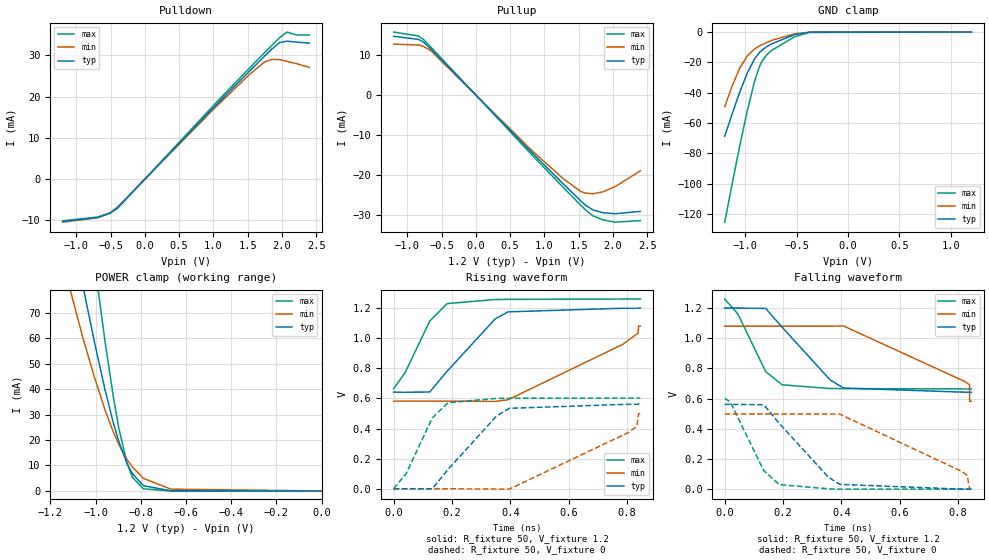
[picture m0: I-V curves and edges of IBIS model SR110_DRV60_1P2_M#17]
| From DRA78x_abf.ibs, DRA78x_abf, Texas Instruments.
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| Model based on original model for DDR_SEIOPB_V
|   Sub model SR110_DRV60_1P2
[model]   SR110_DRV60_1P2_M#17
|[Description]  [1.2V-I/O-X-X]
|   , ,
|[Input Load]
|[Output Drive]
|Voltage   1.2V
|Mode   I/O
Model_type   I/O
Polarity   Non-Inverting
Enable   Active-Low
Vinl =  0.47
Vinh =  0.73
Cref =  15.0000pF
Rref =  100.0000M
Vref =  0V
Vmeas =  0.6
C_comp   2p   2p   2p
[Model Spec]
Vinl   0.47   0.41   0.50
Vinh   0.73   0.67   0.76
[Receiver Thresholds]
Tslew_ac = 5n
Vth = 0.6
Vth_max = 0.63
Vth_min = 0.54
Vinh_ac = 0.22
Vinh_dc = 0.13
Vinl_ac = -0.22
Vinl_dc = -0.13
[Temperature Range]   25   125   -40
[Voltage Range]   1.2   1.08   1.26
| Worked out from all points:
|   slope of the pulldown table from 0 to 0.18 V, typ, clamps not added: 57.2 ohm
|   slope of the pullup table from 0 to 0.18 V, typ, clamps not added: 56.5 ohm
|   GND clamp passes 1 mA (typ) near -0.48 V on its own axis
|   POWER clamp passes 1 mA (typ) near -0.76 V on its own axis
|   rising waveform, R_fixture 50, V_fixture 1.2: 20-80 % time 164ps typ, 322ps min, 88.1ps max; typ from 0.642 V to 1.2 V
|   rising waveform, R_fixture 50, V_fixture 0: 20-80 % time 162ps typ, 307ps min, 87.9ps max; typ from 0 V to 0.562 V
|   falling waveform, R_fixture 50, V_fixture 1.2: 20-80 % time 161ps typ, 295ps min, 88.7ps max; typ from 1.2 V to 0.642 V
|   falling waveform, R_fixture 50, V_fixture 0: 20-80 % time 163ps typ, 312ps min, 89.1ps max; typ from 0.562 V to 0 V
[POWER_clamp]
-1.2V     148.6mA    109.7mA    235.9mA
-1.115V   108mA      79.97mA    170.5mA
-1.055V   80.16mA    59.93mA    125.3mA
-1.006V   59.04mA    45.03mA    90.73mA
-957.6mV  39.59mA    31.69mA    58.49mA
-921.2mV  26.75mA    23.11mA    36.96mA
-897mV    19.41mA    18.26mA    24.7mA
-860.6mV  10.74mA    12.35mA    10.83mA
-836.4mV  6.696mA    9.316mA    5.268mA
-787.9mV  2.052mA    4.939mA    818.3uA
-666.7mV  49.08uA    692.2uA    5.202uA
0V        48.89nA    205.6nA    269.9nA
[Pulldown]
-1.2V     -10.25mA   -10.41mA   -10.07mA
-690.9mV  -9.274mA   -9.358mA   -9.173mA
-509.1mV  -8.227mA   -8.152mA   -8.246mA
-400mV    -6.9mA     -6.78mA    -7.076mA
1.018V    17.59mA    17.2mA     18.12mA
1.527V    26.15mA    25.34mA    26.9mA
1.745V    29.75mA    28.34mA    30.59mA
1.855V    31.52mA    29.01mA    32.41mA
1.964V    33.05mA    28.95mA    34.21mA
2.073V    33.41mA    28.52mA    35.6mA
2.218V    33.15mA    27.94mA    34.88mA
2.4V      32.95mA    27.06mA    34.88mA
[Pullup]
-1.2V     14.78mA    12.82mA    15.83mA
-836.4mV  14mA       12.59mA    14.86mA
-763.6mV  13.3mA     12.22mA    13.97mA
-654.5mV  11.57mA    11.13mA    12.02mA
836.4mV   -14.66mA   -14.11mA   -15.25mA
1.273V    -22.12mA   -20.83mA   -23.01mA
1.527V    -26.37mA   -24.03mA   -27.45mA
1.6V      -27.49mA   -24.48mA   -28.68mA
1.709V    -28.68mA   -24.63mA   -30.17mA
1.855V    -29.39mA   -24.15mA   -31.17mA
2.036V    -29.63mA   -22.8mA    -31.75mA
2.4V      -29.04mA   -18.88mA   -31.34mA
[GND_clamp]
-1.2V     -68.74mA   -49.24mA   -125.5mA
-1.127V   -53.92mA   -35.5mA    -100.1mA
-1.055V   -39.92mA   -23.99mA   -75.5mA
-981.8mV  -27.37mA   -15.83mA   -52.4mA
-909.1mV  -17.63mA   -11.09mA   -32.41mA
-860.6mV  -13.38mA   -9.079mA   -22.59mA
-836.4mV  -11.86mA   -8.241mA   -19.18mA
-787.9mV  -9.515mA   -6.746mA   -14.76mA
-739.4mV  -7.652mA   -5.419mA   -11.95mA
-521.2mV  -1.657mA   -1.168mA   -3.09mA
-375.8mV  -108.2uA   -128.9uA   -198.1uA
1.2V      48.89nA    308.5nA    224.4nA
[Ramp]
dV/dt_f 0.33577288/0.16134658n 0.29997816/0.30428946n 0.35786069/88.819182p
dV/dt_r 0.33946784/0.16323248n 0.30118979/0.3138701n 0.36323897/88.261455p
R_load = 50
[Rising Waveform]
R_fixture = 50
V_fixture = 1.2
V_fixture_min = 1.08
V_fixture_max = 1.26
0s        641.7mV    581.9mV    665mV
39.3ps    641mV      581.9mV    771.3mV
123.8ps   642.6mV    581.8mV    1.114V
183.6ps   781.7mV    581.9mV    1.23V
347.2ps   1.127V     580.4mV    1.257V
391.8ps   1.175V     590.9mV    1.258V
784.8ps   1.199V     958.9mV    1.26V
837.1ps   1.199V     1.033V     1.26V
839.5ps   1.2V       1.08V      1.26V
845.5ps   1.2V       1.08V      1.26V
[Rising Waveform]
R_fixture = 50
V_fixture = 0
V_fixture_min = 0
V_fixture_max = 0
0s        0V         0V         0V
42.9ps    0V         0V         100.9mV
132.3ps   0V         0V         470mV
186.1ps   128.1mV    0V         571.5mV
352.4ps   482.6mV    -2.041mV   600.3mV
396ps     534.2mV    -2.729mV   601mV
804.5ps   561.3mV    373.5mV    602.3mV
833.5ps   561.3mV    415mV      602.3mV
839.3ps   562mV      497.9mV    602.3mV
845.3ps   562mV      497.9mV    602.3mV
[Falling Waveform]
R_fixture = 50
V_fixture = 1.2
V_fixture_min = 1.08
V_fixture_max = 1.26
0s        1.2V       1.08V      1.26V
44.9ps    1.2V       1.08V      1.162V
140.5ps   1.198V     1.08V      778.8mV
197ps     1.073V     1.08V      691.6mV
361.1ps   724.5mV    1.08V      667.1mV
406.8ps   670.4mV    1.082V     666.4mV
822.4ps   642.7mV    713.9mV    664.4mV
839.1ps   642.6mV    692.3mV    664.4mV
839.5ps   641.7mV    581.9mV    664.3mV
845.5ps   641.7mV    581.9mV    664.3mV
[Falling Waveform]
R_fixture = 50
V_fixture = 0
V_fixture_min = 0
V_fixture_max = 0
0s        562mV      497.9mV    601.3mV
18.9ps    562mV      497.9mV    578.9mV
133.8ps   560.1mV    498mV      123.1mV
187.1ps   435.5mV    497.9mV    30.31mV
355.3ps   79.77mV    497.9mV    2.199mV
394ps     31.88mV    497.8mV    0V
813.6ps   0V         116.5mV    0V
831.1ps   0V         91.13mV    0V
839.3ps   0V         0V         0V
845.3ps   0V         0V         0V
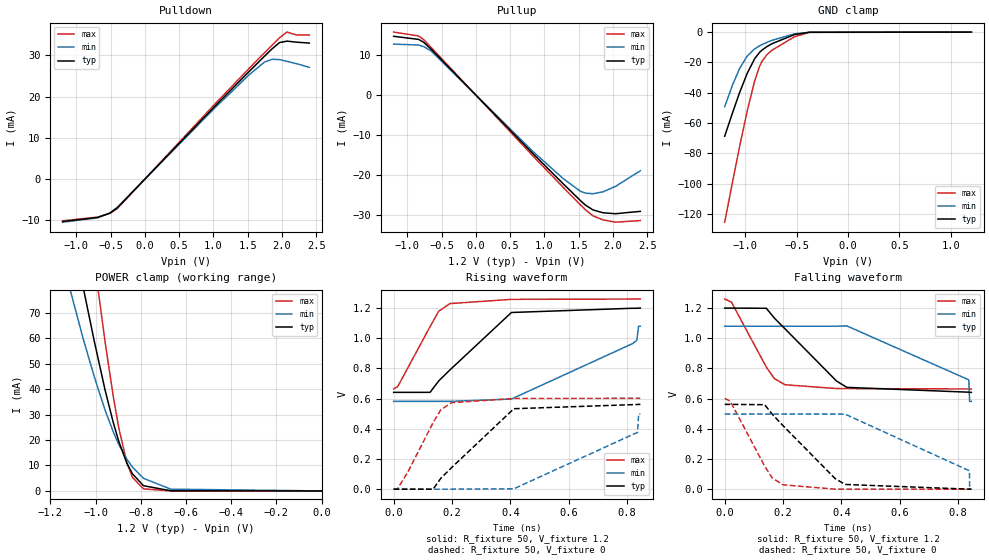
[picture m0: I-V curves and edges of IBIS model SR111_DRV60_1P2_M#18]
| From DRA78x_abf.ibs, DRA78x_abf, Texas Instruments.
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| Model based on original model for DDR_SEIOPB_V
|   Sub model SR111_DRV60_1P2
[model]   SR111_DRV60_1P2_M#18
|[Description]  [1.2V-I/O-X-X]
|   , ,
|[Input Load]
|[Output Drive]
|Voltage   1.2V
|Mode   I/O
Model_type   I/O
Polarity   Non-Inverting
Enable   Active-Low
Vinl =  0.47
Vinh =  0.73
Cref =  15.0000pF
Rref =  100.0000M
Vref =  0V
Vmeas =  0.6
C_comp   2p   2p   2p
[Model Spec]
Vinl   0.47   0.41   0.50
Vinh   0.73   0.67   0.76
[Receiver Thresholds]
Tslew_ac = 5n
Vth = 0.6
Vth_max = 0.63
Vth_min = 0.54
Vinh_ac = 0.22
Vinh_dc = 0.13
Vinl_ac = -0.22
Vinl_dc = -0.13
[Temperature Range]   25   125   -40
[Voltage Range]   1.2   1.08   1.26
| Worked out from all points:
|   slope of the pulldown table from 0 to 0.18 V, typ, clamps not added: 57.2 ohm
|   slope of the pullup table from 0 to 0.18 V, typ, clamps not added: 56.5 ohm
|   GND clamp passes 1 mA (typ) near -0.48 V on its own axis
|   POWER clamp passes 1 mA (typ) near -0.76 V on its own axis
|   rising waveform, R_fixture 50, V_fixture 1.2: 20-80 % time 179ps typ, 347ps min, 95.9ps max; typ from 0.642 V to 1.2 V
|   rising waveform, R_fixture 50, V_fixture 0: 20-80 % time 177ps typ, 316ps min, 95.3ps max; typ from 0 V to 0.562 V
|   falling waveform, R_fixture 50, V_fixture 1.2: 20-80 % time 176ps typ, 286ps min, 96ps max; typ from 1.2 V to 0.642 V
|   falling waveform, R_fixture 50, V_fixture 0: 20-80 % time 178ps typ, 319ps min, 96.7ps max; typ from 0.562 V to 0 V
[POWER_clamp]
-1.2V     148.6mA    109.7mA    235.9mA
-1.115V   108mA      79.97mA    170.5mA
-1.055V   80.16mA    59.93mA    125.3mA
-1.006V   59.04mA    45.03mA    90.73mA
-957.6mV  39.59mA    31.69mA    58.49mA
-921.2mV  26.75mA    23.11mA    36.96mA
-897mV    19.41mA    18.26mA    24.7mA
-860.6mV  10.74mA    12.35mA    10.83mA
-836.4mV  6.696mA    9.316mA    5.268mA
-787.9mV  2.052mA    4.939mA    818.3uA
-666.7mV  49.08uA    692.2uA    5.202uA
0V        48.89nA    205.6nA    269.9nA
[Pulldown]
-1.2V     -10.25mA   -10.41mA   -10.07mA
-690.9mV  -9.274mA   -9.358mA   -9.173mA
-509.1mV  -8.227mA   -8.152mA   -8.246mA
-400mV    -6.9mA     -6.78mA    -7.076mA
1.018V    17.59mA    17.2mA     18.12mA
1.527V    26.15mA    25.34mA    26.9mA
1.745V    29.75mA    28.34mA    30.59mA
1.855V    31.52mA    29.01mA    32.41mA
1.964V    33.05mA    28.95mA    34.21mA
2.073V    33.41mA    28.52mA    35.6mA
2.218V    33.15mA    27.94mA    34.88mA
2.4V      32.95mA    27.06mA    34.88mA
[Pullup]
-1.2V     14.78mA    12.82mA    15.83mA
-836.4mV  14mA       12.59mA    14.86mA
-763.6mV  13.3mA     12.22mA    13.97mA
-654.5mV  11.57mA    11.13mA    12.02mA
836.4mV   -14.66mA   -14.11mA   -15.25mA
1.273V    -22.12mA   -20.83mA   -23.01mA
1.527V    -26.37mA   -24.03mA   -27.45mA
1.6V      -27.49mA   -24.48mA   -28.68mA
1.709V    -28.68mA   -24.63mA   -30.17mA
1.855V    -29.39mA   -24.15mA   -31.17mA
2.036V    -29.63mA   -22.8mA    -31.75mA
2.4V      -29.04mA   -18.88mA   -31.34mA
[GND_clamp]
-1.2V     -68.74mA   -49.24mA   -125.5mA
-1.127V   -53.92mA   -35.5mA    -100.1mA
-1.055V   -39.92mA   -23.99mA   -75.5mA
-981.8mV  -27.37mA   -15.83mA   -52.4mA
-909.1mV  -17.63mA   -11.09mA   -32.41mA
-860.6mV  -13.38mA   -9.079mA   -22.59mA
-836.4mV  -11.86mA   -8.241mA   -19.18mA
-787.9mV  -9.515mA   -6.746mA   -14.76mA
-739.4mV  -7.652mA   -5.419mA   -11.95mA
-521.2mV  -1.657mA   -1.168mA   -3.09mA
-375.8mV  -108.2uA   -128.9uA   -198.1uA
1.2V      48.89nA    308.5nA    224.4nA
[Ramp]
dV/dt_f 0.33583007/0.1769161n 0.29997968/0.32924919n 0.35787335/96.135356p
dV/dt_r 0.33951667/0.17854918n  0.3012481/0.33926419n 0.36316246/95.688566p
R_load = 50
[Rising Waveform]
R_fixture = 50
V_fixture = 1.2
V_fixture_min = 1.08
V_fixture_max = 1.26
0s        641.7mV    581.9mV    664.5mV
14.1ps    641.6mV    581.9mV    680.4mV
124.7ps   641.7mV    581.9mV    1.077V
154.4ps   717.3mV    581.8mV    1.179V
192.8ps   790.1mV    581.9mV    1.23V
403.6ps   1.171V     597.3mV    1.258V
818.3ps   1.199V     964.4mV    1.26V
833.3ps   1.199V     985.9mV    1.26V
839.3ps   1.2V       1.08V      1.26V
845.3ps   1.2V       1.08V      1.26V
[Rising Waveform]
R_fixture = 50
V_fixture = 0
V_fixture_min = 0
V_fixture_max = 0
0s        0V         0V         0V
12.5ps    0V         0V         0V
48.1ps    0V         0V         111.8mV
135.3ps   0V         0V         441.3mV
161.4ps   71.81mV    0V         525.4mV
198.1ps   142.1mV    0V         573.1mV
411.9ps   533.2mV    2.656mV    601.1mV
835.9ps   561.3mV    376.8mV    602.3mV
839.5ps   562mV      497.9mV    602.3mV
845.5ps   562mV      497.9mV    602.3mV
[Falling Waveform]
R_fixture = 50
V_fixture = 1.2
V_fixture_min = 1.08
V_fixture_max = 1.26
0s        1.2V       1.08V      1.26V
23ps      1.2V       1.08V      1.24V
142.7ps   1.199V     1.08V      808.8mV
170.1ps   1.134V     1.08V      733.2mV
206.6ps   1.063V     1.08V      692.2mV
383.3ps   716.6mV    1.08V      666.9mV
418.6ps   674.7mV    1.082V     666.3mV
836.6ps   642.7mV    724.4mV    664.4mV
839.3ps   641.7mV    581.9mV    664.3mV
845.3ps   641.7mV    581.9mV    664.3mV
[Falling Waveform]
R_fixture = 50
V_fixture = 0
V_fixture_min = 0
V_fixture_max = 0
0s        562mV      497.9mV    601.7mV
18.7ps    562mV      497.9mV    583.7mV
136.9ps   559.8mV    498mV      153.2mV
163ps     496.6mV    498mV      74.11mV
199.9ps   420.7mV    497.9mV    28.81mV
378.6ps   70.06mV    498mV      0V
413ps     31.18mV    496.7mV    0V
838.8ps   0V         121.7mV    0V
839.5ps   0V         0V         0V
845.5ps   0V         0V         0V
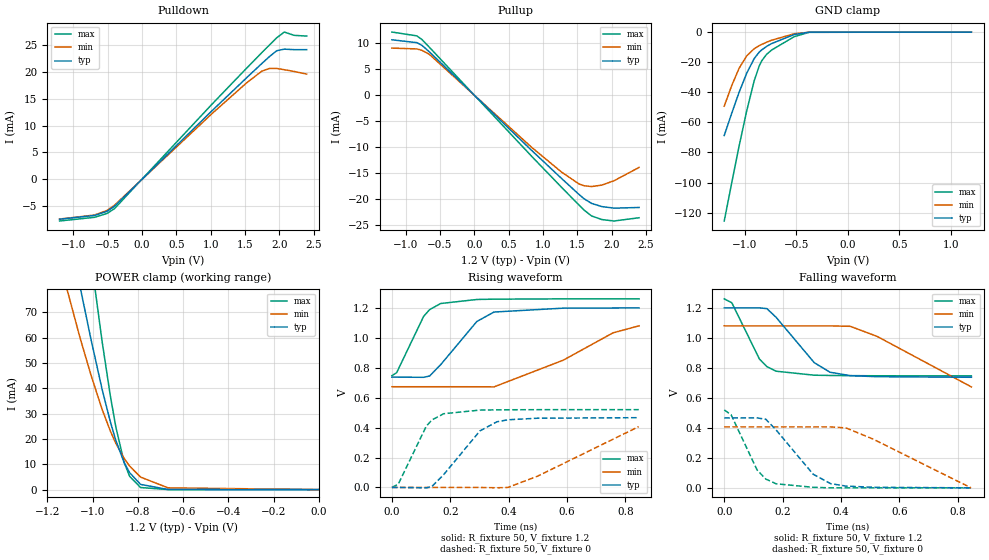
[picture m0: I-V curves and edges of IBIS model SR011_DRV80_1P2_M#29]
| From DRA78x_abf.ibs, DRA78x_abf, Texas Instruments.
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| Model based on original model for DDR_SEIOPB_V
|   Sub model SR011_DRV80_1P2
[model]   SR011_DRV80_1P2_M#29
|[Description]  [1.2V-I/O-X-X]
|   , ,
|[Input Load]
|[Output Drive]
|Voltage   1.2V
|Mode   I/O
Model_type   I/O
Polarity   Non-Inverting
Enable   Active-Low
Vinl =  0.47
Vinh =  0.73
Cref =  15.0000pF
Rref =  100.0000M
Vref =  0V
Vmeas =  0.6
C_comp   2p   2p   2p
[Model Spec]
Vinl   0.47   0.41   0.50
Vinh   0.73   0.67   0.76
[Receiver Thresholds]
Tslew_ac = 5n
Vth = 0.6
Vth_max = 0.63
Vth_min = 0.54
Vinh_ac = 0.22
Vinh_dc = 0.13
Vinl_ac = -0.22
Vinl_dc = -0.13
[Temperature Range]   25   125   -40
[Voltage Range]   1.2   1.08   1.26
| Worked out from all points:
|   slope of the pulldown table from 0 to 0.18 V, typ, clamps not added: 79.2 ohm
|   slope of the pullup table from 0 to 0.18 V, typ, clamps not added: 78.2 ohm
|   GND clamp passes 1 mA (typ) near -0.48 V on its own axis
|   POWER clamp passes 1 mA (typ) near -0.76 V on its own axis
|   rising waveform, R_fixture 50, V_fixture 1.2: 20-80 % time 119ps typ, 250ps min, 78ps max; typ from 0.737 V to 1.2 V
|   rising waveform, R_fixture 50, V_fixture 0: 20-80 % time 119ps typ, 247ps min, 78.2ps max; typ from 0 V to 0.466 V
|   falling waveform, R_fixture 50, V_fixture 1.2: 20-80 % time 120ps typ, 240ps min, 79.1ps max; typ from 1.2 V to 0.737 V
|   falling waveform, R_fixture 50, V_fixture 0: 20-80 % time 120ps typ, 242ps min, 78ps max; typ from 0.466 V to 0 V
[POWER_clamp]
-1.2V     148.6mA    109.7mA    235.9mA
-1.115V   108mA      79.97mA    170.5mA
-1.055V   80.16mA    59.93mA    125.3mA
-1.006V   59.04mA    45.03mA    90.73mA
-957.6mV  39.59mA    31.69mA    58.49mA
-921.2mV  26.75mA    23.11mA    36.96mA
-897mV    19.41mA    18.26mA    24.7mA
-860.6mV  10.74mA    12.35mA    10.83mA
-836.4mV  6.696mA    9.316mA    5.268mA
-787.9mV  2.052mA    4.939mA    818.3uA
-666.7mV  49.08uA    692.2uA    5.202uA
0V        48.89nA    205.6nA    269.9nA
[Pulldown]
-1.2V     -7.405mA   -7.369mA   -7.736mA
-690.9mV  -6.7mA     -6.627mA   -7.049mA
-509.1mV  -5.944mA   -5.774mA   -6.338mA
-400mV    -4.987mA   -4.803mA   -5.44mA
1.018V    12.71mA    12.18mA    13.93mA
1.527V    18.9mA     17.95mA    20.68mA
1.745V    21.5mA     20.08mA    23.52mA
1.855V    22.78mA    20.59mA    24.92mA
1.964V    23.89mA    20.6mA     26.3mA
2.073V    24.18mA    20.36mA    27.36mA
2.218V    24.09mA    20.04mA    26.74mA
2.4V      24.09mA    19.54mA    26.61mA
[Pullup]
-1.2V     10.67mA    9.076mA    12.16mA
-836.4mV  10.12mA    8.913mA    11.42mA
-763.6mV  9.612mA    8.654mA    10.74mA
-654.5mV  8.359mA    7.881mA    9.24mA
836.4mV   -10.59mA   -9.996mA   -11.72mA
1.273V    -15.99mA   -14.76mA   -17.69mA
1.527V    -19.06mA   -17.03mA   -21.1mA
1.6V      -19.87mA   -17.37mA   -22.05mA
1.709V    -20.76mA   -17.52mA   -23.17mA
1.855V    -21.36mA   -17.25mA   -23.85mA
2.036V    -21.67mA   -16.4mA    -24.14mA
2.4V      -21.54mA   -13.85mA   -23.51mA
[GND_clamp]
-1.2V     -68.74mA   -49.24mA   -125.5mA
-1.127V   -53.92mA   -35.5mA    -100.1mA
-1.055V   -39.92mA   -23.99mA   -75.5mA
-981.8mV  -27.37mA   -15.83mA   -52.4mA
-909.1mV  -17.63mA   -11.09mA   -32.41mA
-860.6mV  -13.38mA   -9.079mA   -22.59mA
-836.4mV  -11.86mA   -8.241mA   -19.18mA
-787.9mV  -9.515mA   -6.746mA   -14.76mA
-739.4mV  -7.652mA   -5.419mA   -11.95mA
-521.2mV  -1.657mA   -1.168mA   -3.09mA
-375.8mV  -108.2uA   -128.9uA   -198.1uA
1.2V      48.89nA    308.5nA    224.4nA
[Ramp]
dV/dt_f 0.27812768/0.11982563n 0.24490387/0.24113691n 0.30863571/79.209756p
dV/dt_r 0.28141067/0.11932311n 0.24546317/0.24930007n 0.31390913/78.491417p
R_load = 50
[Rising Waveform]
R_fixture = 50
V_fixture = 1.2
V_fixture_min = 1.08
V_fixture_max = 1.26
0s        737.2mV    673mV      746.6mV
16.3ps    737mV      672.9mV    766.8mV
108.7ps   735.9mV    672.9mV    1.143V
129.1ps   744.6mV    672.9mV    1.188V
167.1ps   820.4mV    672.9mV    1.229V
291ps     1.109V     672.8mV    1.256V
349.6ps   1.172V     671.9mV    1.258V
587.3ps   1.198V     850.6mV    1.26V
757.2ps   1.199V     1.033V     1.26V
846.5ps   1.2V       1.08V      1.26V
[Rising Waveform]
R_fixture = 50
V_fixture = 0
V_fixture_min = 0
V_fixture_max = 0
0s        0V         0V         0V
21.9ps    0V         0V         22.34mV
117.9ps   -2.635mV   0V         409.9mV
137.4ps   7.166mV    0V         451.1mV
177.3ps   85.48mV    0V         492.6mV
301.6ps   378mV      0V         516.9mV
359.6ps   438.7mV    -2.185mV   518.5mV
397ps     452.2mV    0V         519.1mV
498.9ps   462.6mV    75.31mV    519.6mV
845.3ps   466.2mV    406.3mV    520mV
[Falling Waveform]
R_fixture = 50
V_fixture = 1.2
V_fixture_min = 1.08
V_fixture_max = 1.26
0s        1.2V       1.08V      1.26V
26ps      1.2V       1.08V      1.234V
120.4ps   1.2V       1.08V      859.3mV
146.1ps   1.195V     1.08V      808.4mV
177.7ps   1.137V     1.08V      777.7mV
308.4ps   834.4mV    1.08V      751mV
362.3ps   770.9mV    1.08V      749.3mV
431.4ps   748mV      1.077V     748.1mV
523.4ps   741.1mV    1.01V      747.2mV
846.5ps   737.2mV    673mV      746.4mV
[Falling Waveform]
R_fixture = 50
V_fixture = 0
V_fixture_min = 0
V_fixture_max = 0
0s        466.2mV    406.3mV    519.6mV
23.5ps    466.4mV    406.4mV    487.1mV
112.8ps   466.2mV    406.4mV    118.1mV
142.5ps   457.1mV    406.4mV    58.56mV
177.7ps   385.8mV    406.4mV    27.03mV
304.6ps   90.89mV    406.4mV    3.513mV
364.2ps   28.09mV    406.5mV    0V
416.7ps   11.74mV    399.8mV    0V
510.5ps   3.634mV    324.5mV    0V
845.3ps   0V         0V         0V
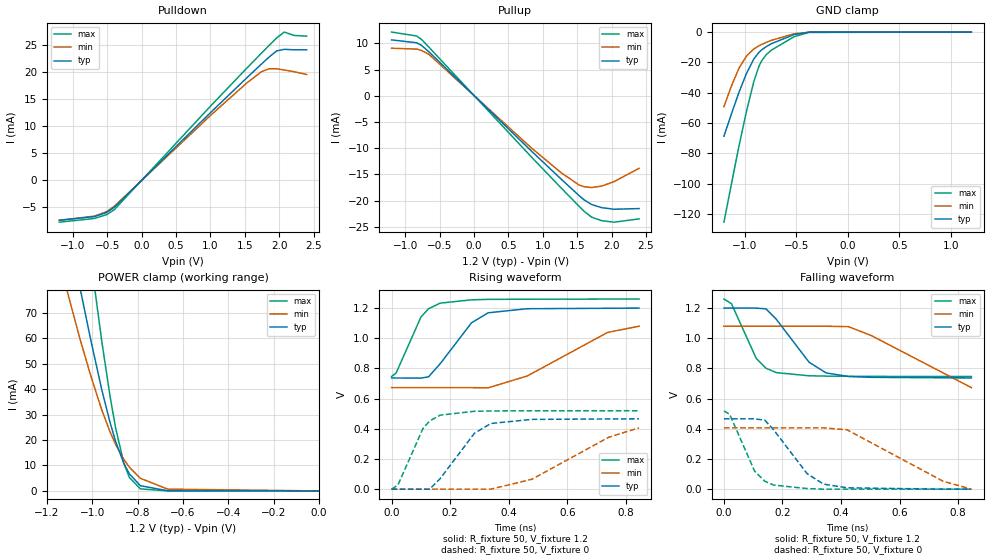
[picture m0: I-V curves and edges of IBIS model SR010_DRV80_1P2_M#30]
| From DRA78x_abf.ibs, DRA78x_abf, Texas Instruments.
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| Model based on original model for DDR_SEIOPB_V
|   Sub model SR010_DRV80_1P2
[model]   SR010_DRV80_1P2_M#30
|[Description]  [1.2V-I/O-X-X]
|   , ,
|[Input Load]
|[Output Drive]
|Voltage   1.2V
|Mode   I/O
Model_type   I/O
Polarity   Non-Inverting
Enable   Active-Low
Vinl =  0.47
Vinh =  0.73
Cref =  15.0000pF
Rref =  100.0000M
Vref =  0V
Vmeas =  0.6
C_comp   2p   2p   2p
[Model Spec]
Vinl   0.47   0.41   0.50
Vinh   0.73   0.67   0.76
[Receiver Thresholds]
Tslew_ac = 5n
Vth = 0.6
Vth_max = 0.63
Vth_min = 0.54
Vinh_ac = 0.22
Vinh_dc = 0.13
Vinl_ac = -0.22
Vinl_dc = -0.13
[Temperature Range]   25   125   -40
[Voltage Range]   1.2   1.08   1.26
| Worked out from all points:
|   slope of the pulldown table from 0 to 0.18 V, typ, clamps not added: 79.2 ohm
|   slope of the pullup table from 0 to 0.18 V, typ, clamps not added: 78.2 ohm
|   GND clamp passes 1 mA (typ) near -0.48 V on its own axis
|   POWER clamp passes 1 mA (typ) near -0.76 V on its own axis
|   rising waveform, R_fixture 50, V_fixture 1.2: 20-80 % time 110ps typ, 232ps min, 72.8ps max; typ from 0.737 V to 1.2 V
|   rising waveform, R_fixture 50, V_fixture 0: 20-80 % time 110ps typ, 230ps min, 72.9ps max; typ from 0 V to 0.466 V
|   falling waveform, R_fixture 50, V_fixture 1.2: 20-80 % time 111ps typ, 223ps min, 74.2ps max; typ from 1.2 V to 0.737 V
|   falling waveform, R_fixture 50, V_fixture 0: 20-80 % time 111ps typ, 224ps min, 73.1ps max; typ from 0.466 V to 0 V
[POWER_clamp]
-1.2V     148.6mA    109.7mA    235.9mA
-1.115V   108mA      79.97mA    170.5mA
-1.055V   80.16mA    59.93mA    125.3mA
-1.006V   59.04mA    45.03mA    90.73mA
-957.6mV  39.59mA    31.69mA    58.49mA
-921.2mV  26.75mA    23.11mA    36.96mA
-897mV    19.41mA    18.26mA    24.7mA
-860.6mV  10.74mA    12.35mA    10.83mA
-836.4mV  6.696mA    9.316mA    5.268mA
-787.9mV  2.052mA    4.939mA    818.3uA
-666.7mV  49.08uA    692.2uA    5.202uA
0V        48.89nA    205.6nA    269.9nA
[Pulldown]
-1.2V     -7.405mA   -7.369mA   -7.736mA
-690.9mV  -6.7mA     -6.627mA   -7.049mA
-509.1mV  -5.944mA   -5.774mA   -6.338mA
-400mV    -4.987mA   -4.803mA   -5.44mA
1.018V    12.71mA    12.18mA    13.93mA
1.527V    18.9mA     17.95mA    20.68mA
1.745V    21.5mA     20.08mA    23.52mA
1.855V    22.78mA    20.59mA    24.92mA
1.964V    23.89mA    20.6mA     26.3mA
2.073V    24.18mA    20.36mA    27.36mA
2.218V    24.09mA    20.04mA    26.74mA
2.4V      24.09mA    19.54mA    26.61mA
[Pullup]
-1.2V     10.67mA    9.076mA    12.16mA
-836.4mV  10.12mA    8.913mA    11.42mA
-763.6mV  9.612mA    8.654mA    10.74mA
-654.5mV  8.359mA    7.881mA    9.24mA
836.4mV   -10.59mA   -9.996mA   -11.72mA
1.273V    -15.99mA   -14.76mA   -17.69mA
1.527V    -19.06mA   -17.03mA   -21.1mA
1.6V      -19.87mA   -17.37mA   -22.05mA
1.709V    -20.76mA   -17.52mA   -23.17mA
1.855V    -21.36mA   -17.25mA   -23.85mA
2.036V    -21.67mA   -16.4mA    -24.14mA
2.4V      -21.54mA   -13.85mA   -23.51mA
[GND_clamp]
-1.2V     -68.74mA   -49.24mA   -125.5mA
-1.127V   -53.92mA   -35.5mA    -100.1mA
-1.055V   -39.92mA   -23.99mA   -75.5mA
-981.8mV  -27.37mA   -15.83mA   -52.4mA
-909.1mV  -17.63mA   -11.09mA   -32.41mA
-860.6mV  -13.38mA   -9.079mA   -22.59mA
-836.4mV  -11.86mA   -8.241mA   -19.18mA
-787.9mV  -9.515mA   -6.746mA   -14.76mA
-739.4mV  -7.652mA   -5.419mA   -11.95mA
-521.2mV  -1.657mA   -1.168mA   -3.09mA
-375.8mV  -108.2uA   -128.9uA   -198.1uA
1.2V      48.89nA    308.5nA    224.4nA
[Ramp]
dV/dt_f 0.27808599/0.11117335n 0.24487076/0.22409488n 0.30862439/74.272178p
dV/dt_r 0.28139213/0.11029676n 0.24544543/0.23162482n 0.31405468/73.198538p
R_load = 50
[Rising Waveform]
R_fixture = 50
V_fixture = 1.2
V_fixture_min = 1.08
V_fixture_max = 1.26
0s        737.2mV    673mV      747.1mV
15.4ps    736.9mV    672.9mV    770mV
100.5ps   736mV      672.9mV    1.142V
126.3ps   744.8mV    672.9mV    1.196V
166ps     831.5mV    672.9mV    1.233V
273.2ps   1.103V     672.8mV    1.255V
330ps     1.169V     671.9mV    1.258V
463.2ps   1.196V     749.9mV    1.259V
738.1ps   1.199V     1.039V     1.26V
845.5ps   1.2V       1.08V      1.26V
[Rising Waveform]
R_fixture = 50
V_fixture = 0
V_fixture_min = 0
V_fixture_max = 0
0s        0V         0V         0V
21.7ps    0V         0V         27.79mV
107.3ps   0V         0V         402.7mV
130ps     0V         0V         452.2mV
165.9ps   69.85mV    0V         490.5mV
282.9ps   370.2mV    0V         516.4mV
339.2ps   435.4mV    0V         518.3mV
479.1ps   462.4mV    65.49mV    519.5mV
742.6ps   465.5mV    344.8mV    520mV
845.3ps   466.2mV    406.3mV    520mV
[Falling Waveform]
R_fixture = 50
V_fixture = 1.2
V_fixture_min = 1.08
V_fixture_max = 1.26
0s        1.2V       1.08V      1.26V
25.5ps    1.2V       1.08V      1.23V
110.5ps   1.2V       1.08V      866.2mV
143.4ps   1.195V     1.08V      802mV
178.5ps   1.127V     1.08V      772.6mV
290.6ps   841.9mV    1.08V      751.5mV
349ps     770.4mV    1.08V      749.4mV
425.8ps   746.8mV    1.077V     748.1mV
504.7ps   741.2mV    1.017V     747.3mV
845.5ps   737.2mV    673mV      746.4mV
[Falling Waveform]
R_fixture = 50
V_fixture = 0
V_fixture_min = 0
V_fixture_max = 0
0s        466.2mV    406.3mV    519.2mV
19.5ps    466.4mV    406.4mV    496.3mV
104.8ps   466.1mV    406.4mV    119.5mV
139.8ps   457.1mV    406.4mV    52.34mV
169.9ps   393.3mV    406.4mV    27.06mV
284.2ps   102.8mV    406.4mV    4.039mV
340.2ps   33.58mV    406.4mV    0V
420.6ps   8.983mV    393.5mV    0V
748.2ps   0V         53.19mV    0V
845.3ps   0V         0V         0V
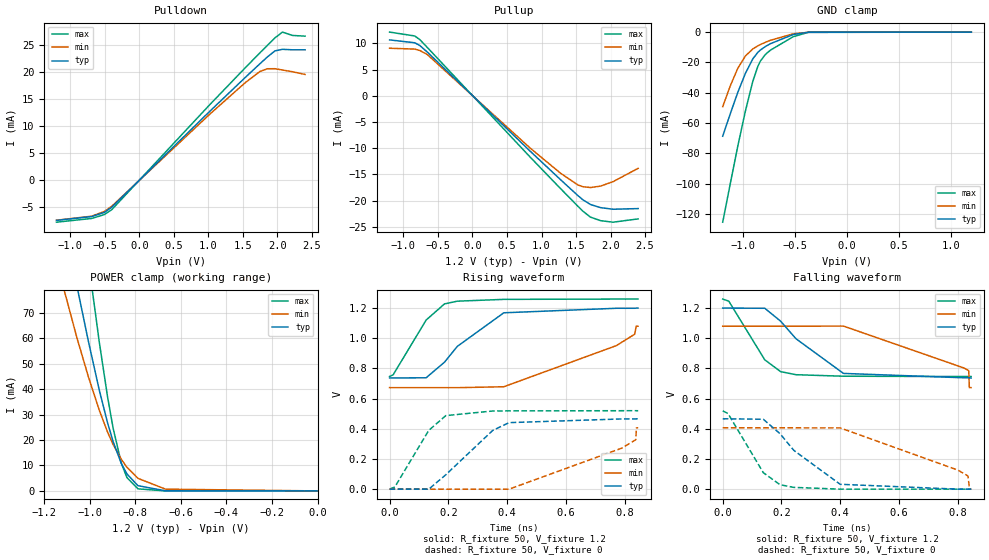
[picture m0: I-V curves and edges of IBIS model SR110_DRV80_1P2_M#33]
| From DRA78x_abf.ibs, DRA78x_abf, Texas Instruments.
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| Model based on original model for DDR_SEIOPB_V
|   Sub model SR110_DRV80_1P2
[model]   SR110_DRV80_1P2_M#33
|[Description]  [1.2V-I/O-X-X]
|   , ,
|[Input Load]
|[Output Drive]
|Voltage   1.2V
|Mode   I/O
Model_type   I/O
Polarity   Non-Inverting
Enable   Active-Low
Vinl =  0.47
Vinh =  0.73
Cref =  15.0000pF
Rref =  100.0000M
Vref =  0V
Vmeas =  0.6
C_comp   2p   2p   2p
[Model Spec]
Vinl   0.47   0.41   0.50
Vinh   0.73   0.67   0.76
[Receiver Thresholds]
Tslew_ac = 5n
Vth = 0.6
Vth_max = 0.63
Vth_min = 0.54
Vinh_ac = 0.22
Vinh_dc = 0.13
Vinl_ac = -0.22
Vinl_dc = -0.13
[Temperature Range]   25   125   -40
[Voltage Range]   1.2   1.08   1.26
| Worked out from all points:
|   slope of the pulldown table from 0 to 0.18 V, typ, clamps not added: 79.2 ohm
|   slope of the pullup table from 0 to 0.18 V, typ, clamps not added: 78.2 ohm
|   GND clamp passes 1 mA (typ) near -0.48 V on its own axis
|   POWER clamp passes 1 mA (typ) near -0.76 V on its own axis
|   rising waveform, R_fixture 50, V_fixture 1.2: 20-80 % time 155ps typ, 308ps min, 99ps max; typ from 0.737 V to 1.2 V
|   rising waveform, R_fixture 50, V_fixture 0: 20-80 % time 152ps typ, 303ps min, 98.6ps max; typ from 0 V to 0.466 V
|   falling waveform, R_fixture 50, V_fixture 1.2: 20-80 % time 152ps typ, 272ps min, 99ps max; typ from 1.2 V to 0.737 V
|   falling waveform, R_fixture 50, V_fixture 0: 20-80 % time 155ps typ, 299ps min, 98.6ps max; typ from 0.466 V to 0 V
[POWER_clamp]
-1.2V     148.6mA    109.7mA    235.9mA
-1.115V   108mA      79.97mA    170.5mA
-1.055V   80.16mA    59.93mA    125.3mA
-1.006V   59.04mA    45.03mA    90.73mA
-957.6mV  39.59mA    31.69mA    58.49mA
-921.2mV  26.75mA    23.11mA    36.96mA
-897mV    19.41mA    18.26mA    24.7mA
-860.6mV  10.74mA    12.35mA    10.83mA
-836.4mV  6.696mA    9.316mA    5.268mA
-787.9mV  2.052mA    4.939mA    818.3uA
-666.7mV  49.08uA    692.2uA    5.202uA
0V        48.89nA    205.6nA    269.9nA
[Pulldown]
-1.2V     -7.405mA   -7.369mA   -7.736mA
-690.9mV  -6.7mA     -6.627mA   -7.049mA
-509.1mV  -5.944mA   -5.774mA   -6.338mA
-400mV    -4.987mA   -4.803mA   -5.44mA
1.018V    12.71mA    12.18mA    13.93mA
1.527V    18.9mA     17.95mA    20.68mA
1.745V    21.5mA     20.08mA    23.52mA
1.855V    22.78mA    20.59mA    24.92mA
1.964V    23.89mA    20.6mA     26.3mA
2.073V    24.18mA    20.36mA    27.36mA
2.218V    24.09mA    20.04mA    26.74mA
2.4V      24.09mA    19.54mA    26.61mA
[Pullup]
-1.2V     10.67mA    9.076mA    12.16mA
-836.4mV  10.12mA    8.913mA    11.42mA
-763.6mV  9.612mA    8.654mA    10.74mA
-654.5mV  8.359mA    7.881mA    9.24mA
836.4mV   -10.59mA   -9.996mA   -11.72mA
1.273V    -15.99mA   -14.76mA   -17.69mA
1.527V    -19.06mA   -17.03mA   -21.1mA
1.6V      -19.87mA   -17.37mA   -22.05mA
1.709V    -20.76mA   -17.52mA   -23.17mA
1.855V    -21.36mA   -17.25mA   -23.85mA
2.036V    -21.67mA   -16.4mA    -24.14mA
2.4V      -21.54mA   -13.85mA   -23.51mA
[GND_clamp]
-1.2V     -68.74mA   -49.24mA   -125.5mA
-1.127V   -53.92mA   -35.5mA    -100.1mA
-1.055V   -39.92mA   -23.99mA   -75.5mA
-981.8mV  -27.37mA   -15.83mA   -52.4mA
-909.1mV  -17.63mA   -11.09mA   -32.41mA
-860.6mV  -13.38mA   -9.079mA   -22.59mA
-836.4mV  -11.86mA   -8.241mA   -19.18mA
-787.9mV  -9.515mA   -6.746mA   -14.76mA
-739.4mV  -7.652mA   -5.419mA   -11.95mA
-521.2mV  -1.657mA   -1.168mA   -3.09mA
-375.8mV  -108.2uA   -128.9uA   -198.1uA
1.2V      48.89nA    308.5nA    224.4nA
[Ramp]
dV/dt_f 0.27821403/0.15270574n 0.24499218/0.2978185n 0.30873683/99.20106p
dV/dt_r 0.28134874/0.15322759n 0.24553615/0.30567669n 0.31391762/99.122188p
R_load = 50
[Rising Waveform]
R_fixture = 50
V_fixture = 1.2
V_fixture_min = 1.08
V_fixture_max = 1.26
0s        737.2mV    673mV      746.8mV
12.4ps    737.1mV    672.9mV    758.7mV
124.4ps   738.3mV    672.9mV    1.121V
186.9ps   841.7mV    673mV      1.228V
230.6ps   946.5mV    672.7mV    1.246V
388.7ps   1.169V     678.8mV    1.258V
771.9ps   1.199V     951.5mV    1.26V
834.1ps   1.199V     1.027V     1.26V
839.3ps   1.2V       1.08V      1.26V
845.3ps   1.2V       1.08V      1.26V
[Rising Waveform]
R_fixture = 50
V_fixture = 0
V_fixture_min = 0
V_fixture_max = 0
0s        0V         0V         0V
17.9ps    0V         0V         14.6mV
133.3ps   0V         0V         389.6mV
191.5ps   95.85mV    0V         487.6mV
350.8ps   389mV      0V         518.1mV
406.6ps   441mV      0V         518.9mV
790.8ps   465.5mV    272.3mV    520mV
837.9ps   465.7mV    327.9mV    520.1mV
840.1ps   466.2mV    406.3mV    520mV
846.1ps   466.2mV    406.3mV    520mV
[Falling Waveform]
R_fixture = 50
V_fixture = 1.2
V_fixture_min = 1.08
V_fixture_max = 1.26
0s        1.2V       1.08V      1.26V
20.7ps    1.2V       1.08V      1.246V
143.1ps   1.199V     1.08V      857.4mV
197.4ps   1.113V     1.08V      778.8mV
249.6ps   996.6mV    1.08V      758.6mV
411ps     767.2mV    1.081V     748.6mV
821ps     738.2mV    803.2mV    746.4mV
837.3ps   738.2mV    785.8mV    746.4mV
839.3ps   737.2mV    673mV      746.4mV
845.3ps   737.2mV    673mV      746.4mV
[Falling Waveform]
R_fixture = 50
V_fixture = 0
V_fixture_min = 0
V_fixture_max = 0
0s        466.2mV    406.3mV    519.1mV
17.9ps    466.3mV    406.4mV    501.7mV
138.2ps   463.3mV    406.4mV    109.3mV
194.9ps   368mV      406.4mV    29.61mV
242.2ps   256.8mV    406.4mV    11.79mV
399.8ps   32.28mV    406mV      0V
800.8ps   0V         126mV      0V
834.8ps   0V         87.1mV     0V
840.1ps   0V         0V         0V
846.1ps   0V         0V         0V
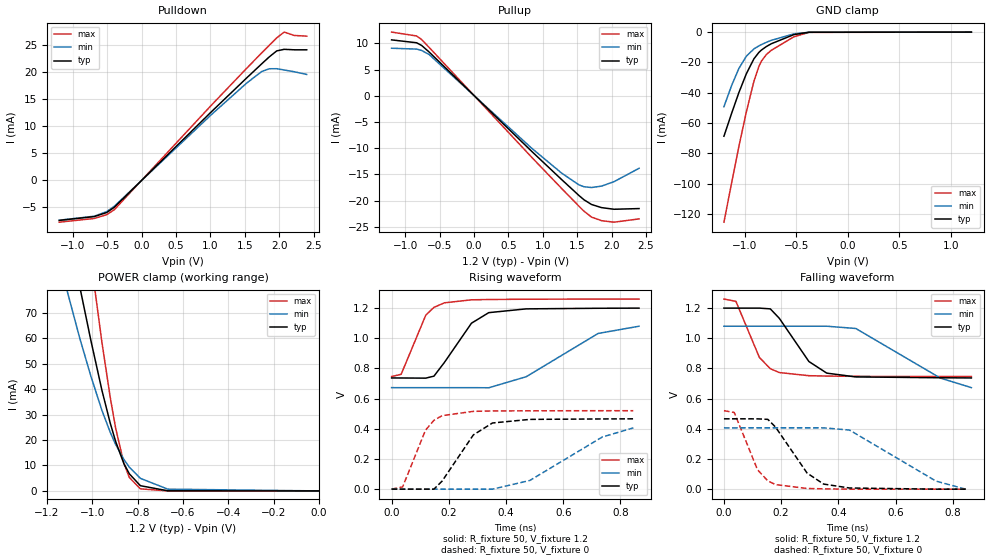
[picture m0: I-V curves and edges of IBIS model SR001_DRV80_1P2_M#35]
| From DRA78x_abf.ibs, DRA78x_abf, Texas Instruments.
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| Model based on original model for DDR_SEIOPB_V
|   Sub model SR001_DRV80_1P2
[model]   SR001_DRV80_1P2_M#35
|[Description]  [1.2V-I/O-X-X]
|   , ,
|[Input Load]
|[Output Drive]
|Voltage   1.2V
|Mode   I/O
Model_type   I/O
Polarity   Non-Inverting
Enable   Active-Low
Vinl =  0.47
Vinh =  0.73
Cref =  15.0000pF
Rref =  100.0000M
Vref =  0V
Vmeas =  0.6
C_comp   2p   2p   2p
[Model Spec]
Vinl   0.47   0.41   0.50
Vinh   0.73   0.67   0.76
[Receiver Thresholds]
Tslew_ac = 5n
Vth = 0.6
Vth_max = 0.63
Vth_min = 0.54
Vinh_ac = 0.22
Vinh_dc = 0.13
Vinl_ac = -0.22
Vinl_dc = -0.13
[Temperature Range]   25   125   -40
[Voltage Range]   1.2   1.08   1.26
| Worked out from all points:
|   slope of the pulldown table from 0 to 0.18 V, typ, clamps not added: 79.2 ohm
|   slope of the pullup table from 0 to 0.18 V, typ, clamps not added: 78.2 ohm
|   GND clamp passes 1 mA (typ) near -0.48 V on its own axis
|   POWER clamp passes 1 mA (typ) near -0.76 V on its own axis
|   rising waveform, R_fixture 50, V_fixture 1.2: 20-80 % time 102ps typ, 213ps min, 68.5ps max; typ from 0.737 V to 1.2 V
|   rising waveform, R_fixture 50, V_fixture 0: 20-80 % time 102ps typ, 212ps min, 68.6ps max; typ from 0 V to 0.466 V
|   falling waveform, R_fixture 50, V_fixture 1.2: 20-80 % time 103ps typ, 207ps min, 70.4ps max; typ from 1.2 V to 0.737 V
|   falling waveform, R_fixture 50, V_fixture 0: 20-80 % time 103ps typ, 207ps min, 69.2ps max; typ from 0.466 V to 0 V
[POWER_clamp]
-1.2V     148.6mA    109.7mA    235.9mA
-1.115V   108mA      79.97mA    170.5mA
-1.055V   80.16mA    59.93mA    125.3mA
-1.006V   59.04mA    45.03mA    90.73mA
-957.6mV  39.59mA    31.69mA    58.49mA
-921.2mV  26.75mA    23.11mA    36.96mA
-897mV    19.41mA    18.26mA    24.7mA
-860.6mV  10.74mA    12.35mA    10.83mA
-836.4mV  6.696mA    9.316mA    5.268mA
-787.9mV  2.052mA    4.939mA    818.3uA
-666.7mV  49.08uA    692.2uA    5.202uA
0V        48.89nA    205.6nA    269.9nA
[Pulldown]
-1.2V     -7.405mA   -7.369mA   -7.736mA
-690.9mV  -6.7mA     -6.627mA   -7.049mA
-509.1mV  -5.944mA   -5.774mA   -6.338mA
-400mV    -4.987mA   -4.803mA   -5.44mA
1.018V    12.71mA    12.18mA    13.93mA
1.527V    18.9mA     17.95mA    20.68mA
1.745V    21.5mA     20.08mA    23.52mA
1.855V    22.78mA    20.59mA    24.92mA
1.964V    23.89mA    20.6mA     26.3mA
2.073V    24.18mA    20.36mA    27.36mA
2.218V    24.09mA    20.04mA    26.74mA
2.4V      24.09mA    19.54mA    26.61mA
[Pullup]
-1.2V     10.67mA    9.076mA    12.16mA
-836.4mV  10.12mA    8.913mA    11.42mA
-763.6mV  9.612mA    8.654mA    10.74mA
-654.5mV  8.359mA    7.881mA    9.24mA
836.4mV   -10.59mA   -9.996mA   -11.72mA
1.273V    -15.99mA   -14.76mA   -17.69mA
1.527V    -19.06mA   -17.03mA   -21.1mA
1.6V      -19.87mA   -17.37mA   -22.05mA
1.709V    -20.76mA   -17.52mA   -23.17mA
1.855V    -21.36mA   -17.25mA   -23.85mA
2.036V    -21.67mA   -16.4mA    -24.14mA
2.4V      -21.54mA   -13.85mA   -23.51mA
[GND_clamp]
-1.2V     -68.74mA   -49.24mA   -125.5mA
-1.127V   -53.92mA   -35.5mA    -100.1mA
-1.055V   -39.92mA   -23.99mA   -75.5mA
-981.8mV  -27.37mA   -15.83mA   -52.4mA
-909.1mV  -17.63mA   -11.09mA   -32.41mA
-860.6mV  -13.38mA   -9.079mA   -22.59mA
-836.4mV  -11.86mA   -8.241mA   -19.18mA
-787.9mV  -9.515mA   -6.746mA   -14.76mA
-739.4mV  -7.652mA   -5.419mA   -11.95mA
-521.2mV  -1.657mA   -1.168mA   -3.09mA
-375.8mV  -108.2uA   -128.9uA   -198.1uA
1.2V      48.89nA    308.5nA    224.4nA
[Ramp]
dV/dt_f 0.27806464/0.10315079n  0.2448486/0.20721136n 0.30860795/70.456874p
dV/dt_r 0.28140726/0.10195844n 0.24544271/0.21359993n 0.31408135/68.898306p
R_load = 50
[Rising Waveform]
R_fixture = 50
V_fixture = 1.2
V_fixture_min = 1.08
V_fixture_max = 1.26
0s        737.2mV    673mV      746.4mV
33.4ps    736.9mV    672.9mV    761.4mV
119.4ps   735.9mV    672.9mV    1.153V
148ps     749.1mV    672.9mV    1.205V
184.4ps   839.5mV    672.9mV    1.235V
279.2ps   1.1V       672.8mV    1.255V
339.6ps   1.17V      672.1mV    1.257V
470.7ps   1.195V     745.3mV    1.259V
721.9ps   1.199V     1.032V     1.26V
865.1ps   1.2V       1.08V      1.26V
[Rising Waveform]
R_fixture = 50
V_fixture = 0
V_fixture_min = 0
V_fixture_max = 0
0s        0V         0V         0V
38.5ps    0V         0V         14.92mV
118.6ps   0V         0V         391.2mV
147.8ps   0V         0V         456.2mV
176.5ps   53.36mV    0V         487.4mV
285.8ps   359.7mV    0V         515.7mV
352.6ps   438.6mV    0V         518.3mV
483.4ps   462.5mV    57.77mV    519.5mV
736.4ps   465.4mV    345.5mV    520mV
845.3ps   466.2mV    406.3mV    520mV
[Falling Waveform]
R_fixture = 50
V_fixture = 1.2
V_fixture_min = 1.08
V_fixture_max = 1.26
0s        1.2V       1.08V      1.26V
41.8ps    1.2V       1.08V      1.245V
123.9ps   1.2V       1.08V      873.1mV
162.1ps   1.195V     1.08V      798.5mV
193.8ps   1.132V     1.08V      772.8mV
297ps     846.1mV    1.08V      752.1mV
359.5ps   769.1mV    1.08V      749.6mV
461ps     744mV      1.065V     747.8mV
756.6ps   738.4mV    736.4mV    746.5mV
865.1ps   737.2mV    673mV      746.4mV
[Falling Waveform]
R_fixture = 50
V_fixture = 0
V_fixture_min = 0
V_fixture_max = 0
0s        466.2mV    406.3mV    520mV
36ps      466.4mV    406.4mV    508.3mV
117.5ps   466mV      406.5mV    128.2mV
153.5ps   462.6mV    406.5mV    54.87mV
180.3ps   411.7mV    406.5mV    30.24mV
290.8ps   106.4mV    406.5mV    4.572mV
348.6ps   33.65mV    406.4mV    2.189mV
438.9ps   7.786mV    391.8mV    0V
741.5ps   0V         53.35mV    0V
845.3ps   0V         0V         0V
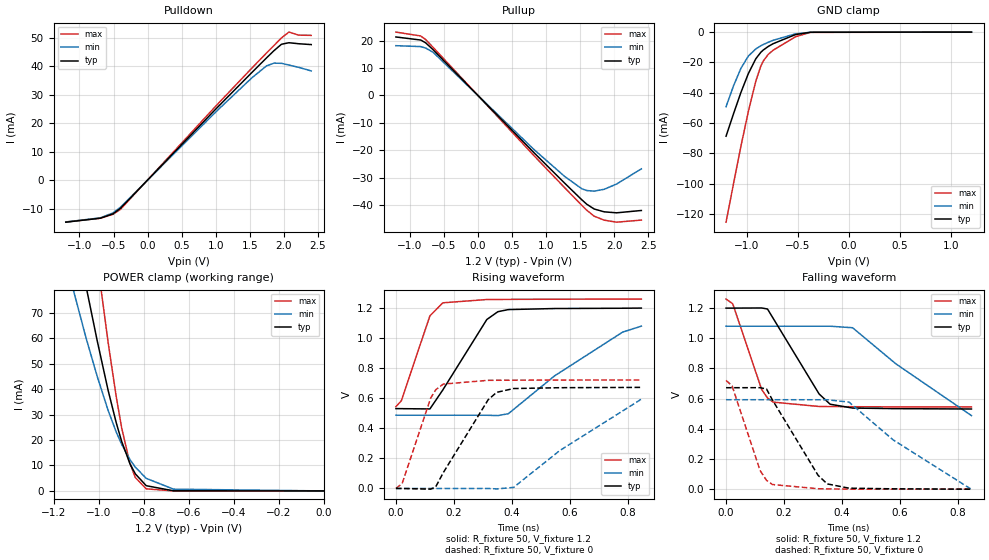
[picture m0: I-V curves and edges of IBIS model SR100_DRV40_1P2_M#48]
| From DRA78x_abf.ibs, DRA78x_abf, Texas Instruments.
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| Model based on original model for DDR_SEIOPB_V
|   Sub model SR100_DRV40_1P2
[model]   SR100_DRV40_1P2_M#48
|[Description]  [1.2V-I/O-X-X]
|   , ,
|[Input Load]
|[Output Drive]
|Voltage   1.2V
|Mode   I/O
Model_type   I/O
Polarity   Non-Inverting
Enable   Active-Low
Vinl =  0.47
Vinh =  0.73
Cref =  15.0000pF
Rref =  100.0000M
Vref =  0V
Vmeas =  0.6
C_comp   2p   2p   2p
[Model Spec]
Vinl   0.47   0.41   0.50
Vinh   0.73   0.67   0.76
[Receiver Thresholds]
Tslew_ac = 5n
Vth = 0.6
Vth_max = 0.63
Vth_min = 0.54
Vinh_ac = 0.22
Vinh_dc = 0.13
Vinl_ac = -0.22
Vinl_dc = -0.13
[Temperature Range]   25   125   -40
[Voltage Range]   1.2   1.08   1.26
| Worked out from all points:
|   slope of the pulldown table from 0 to 0.18 V, typ, clamps not added: 39.6 ohm
|   slope of the pullup table from 0 to 0.18 V, typ, clamps not added: 39.1 ohm
|   GND clamp passes 1 mA (typ) near -0.48 V on its own axis
|   POWER clamp passes 1 mA (typ) near -0.76 V on its own axis
|   rising waveform, R_fixture 50, V_fixture 1.2: 20-80 % time 131ps typ, 290ps min, 73ps max; typ from 0.531 V to 1.2 V
|   rising waveform, R_fixture 50, V_fixture 0: 20-80 % time 129ps typ, 284ps min, 72.7ps max; typ from 0 V to 0.672 V
|   falling waveform, R_fixture 50, V_fixture 1.2: 20-80 % time 128ps typ, 276ps min, 72.8ps max; typ from 1.2 V to 0.531 V
|   falling waveform, R_fixture 50, V_fixture 0: 20-80 % time 130ps typ, 280ps min, 72.9ps max; typ from 0.672 V to 0 V
[POWER_clamp]
-1.2V     148.6mA    109.7mA    235.9mA
-1.115V   108mA      79.97mA    170.5mA
-1.055V   80.16mA    59.93mA    125.3mA
-1.006V   59.04mA    45.03mA    90.73mA
-957.6mV  39.59mA    31.69mA    58.49mA
-921.2mV  26.75mA    23.11mA    36.96mA
-897mV    19.41mA    18.26mA    24.7mA
-860.6mV  10.74mA    12.35mA    10.83mA
-836.4mV  6.696mA    9.316mA    5.268mA
-787.9mV  2.052mA    4.939mA    818.3uA
-666.7mV  49.08uA    692.2uA    5.202uA
0V        48.89nA    205.6nA    269.9nA
[Pulldown]
-1.2V     -14.8mA    -14.74mA   -14.71mA
-690.9mV  -13.39mA   -13.26mA   -13.4mA
-509.1mV  -11.88mA   -11.54mA   -12.04mA
-400mV    -9.96mA    -9.599mA   -10.33mA
1.018V    25.39mA    24.35mA    26.45mA
1.527V    37.74mA    35.87mA    39.28mA
1.745V    42.94mA    40.13mA    44.66mA
1.855V    45.5mA     41.09mA    47.32mA
1.964V    47.72mA    41.01mA    49.95mA
2.073V    48.25mA    40.41mA    51.99mA
2.218V    47.89mA    39.59mA    50.92mA
2.4V      47.6mA     38.35mA    50.84mA
[Pullup]
-1.2V     21.34mA    18.16mA    23.12mA
-836.4mV  20.22mA    17.83mA    21.7mA
-763.6mV  19.2mA     17.3mA     20.39mA
-654.5mV  16.69mA    15.75mA    17.55mA
836.4mV   -21.16mA   -19.98mA   -22.26mA
1.273V    -31.93mA   -29.49mA   -33.59mA
1.527V    -38.06mA   -34.03mA   -40.07mA
1.6V      -39.68mA   -34.68mA   -41.87mA
1.709V    -41.42mA   -34.9mA    -44.05mA
1.855V    -42.44mA   -34.22mA   -45.47mA
2.036V    -42.8mA    -32.31mA   -46.22mA
2.4V      -41.95mA   -26.76mA   -45.45mA
[GND_clamp]
-1.2V     -68.74mA   -49.24mA   -125.5mA
-1.127V   -53.92mA   -35.5mA    -100.1mA
-1.055V   -39.92mA   -23.99mA   -75.5mA
-981.8mV  -27.37mA   -15.83mA   -52.4mA
-909.1mV  -17.63mA   -11.09mA   -32.41mA
-860.6mV  -13.38mA   -9.079mA   -22.59mA
-836.4mV  -11.86mA   -8.241mA   -19.18mA
-787.9mV  -9.515mA   -6.746mA   -14.76mA
-739.4mV  -7.652mA   -5.419mA   -11.95mA
-521.2mV  -1.657mA   -1.168mA   -3.09mA
-375.8mV  -108.2uA   -128.9uA   -198.1uA
1.2V      48.89nA    308.5nA    224.4nA
[Ramp]
dV/dt_f 0.40213173/0.12841028n 0.35706858/0.27756794n 0.42967972/72.895983p
dV/dt_r 0.40630662/0.1302606n 0.35917543/0.28707827n 0.43545268/73.158921p
R_load = 50
[Rising Waveform]
R_fixture = 50
V_fixture = 1.2
V_fixture_min = 1.08
V_fixture_max = 1.26
0s        531.3mV    487.5mV    544.6mV
18.5ps    530.9mV    487.5mV    582.9mV
117.2ps   529.1mV    487.4mV    1.148V
161.7ps   655.4mV    487.5mV    1.235V
313.5ps   1.124V     487mV      1.257V
351.7ps   1.176V     484.9mV    1.257V
387.6ps   1.19V      497.2mV    1.258V
547.5ps   1.197V     749.5mV    1.259V
781.8ps   1.199V     1.04V      1.26V
846.5ps   1.2V       1.08V      1.26V
[Rising Waveform]
R_fixture = 50
V_fixture = 0
V_fixture_min = 0
V_fixture_max = 0
0s        0V         0V         0V
21.6ps    0V         0V         33.8mV
120.1ps   -4.619mV   0V         602.7mV
137.4ps   11.62mV    0V         656.7mV
163.5ps   105.7mV    0V         694.5mV
317.9ps   589.6mV    0V         719.3mV
347.2ps   639.4mV    -3.001mV   719.8mV
405.6ps   664.7mV    7.075mV    720.3mV
565.1ps   670.4mV    252.1mV    721.2mV
845.3ps   672.4mV    592.8mV    721.6mV
[Falling Waveform]
R_fixture = 50
V_fixture = 1.2
V_fixture_min = 1.08
V_fixture_max = 1.26
0s        1.2V       1.08V      1.26V
23ps      1.2V       1.08V      1.229V
122.7ps   1.201V     1.08V      661.6mV
143ps     1.194V     1.08V      604.3mV
162.6ps   1.132V     1.08V      576.9mV
320.9ps   631.1mV    1.08V      548mV
359ps     563mV      1.08V      547.3mV
436.4ps   537.5mV    1.07V      546.4mV
585.1ps   533.7mV    831.5mV    545.4mV
846.5ps   531.3mV    487.5mV    544.9mV
[Falling Waveform]
R_fixture = 50
V_fixture = 0
V_fixture_min = 0
V_fixture_max = 0
0s        672.4mV    592.8mV    721mV
20.9ps    672.5mV    592.8mV    684.7mV
117.1ps   672.7mV    592.8mV    124.7mV
139.6ps   663.8mV    592.8mV    58.05mV
160ps     591.3mV    592.8mV    30.74mV
317.6ps   91.23mV    592.6mV    2.805mV
349.1ps   34.86mV    592.7mV    2.129mV
424ps     6.642mV    577mV      0V
576ps     2.205mV    327.1mV    0V
845.3ps   0V         0V         0V
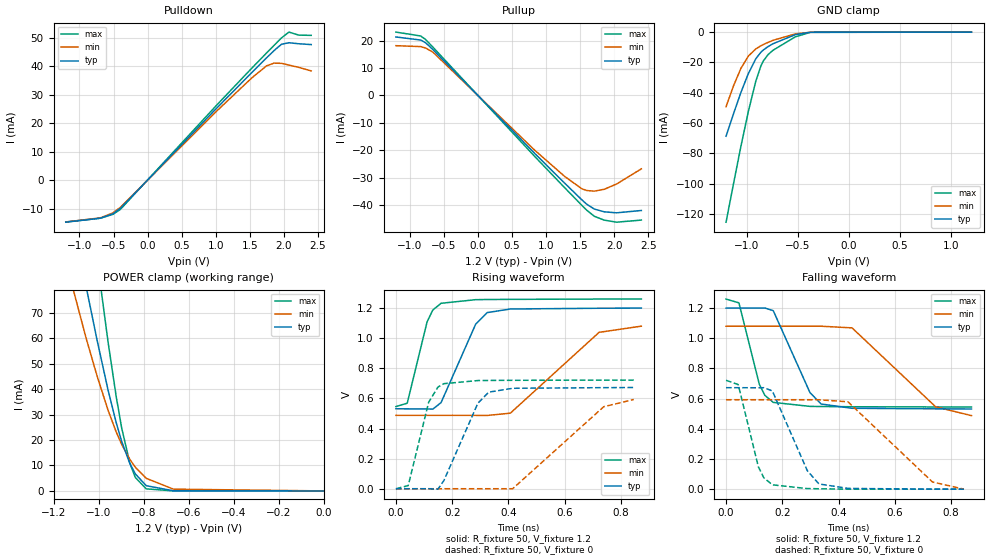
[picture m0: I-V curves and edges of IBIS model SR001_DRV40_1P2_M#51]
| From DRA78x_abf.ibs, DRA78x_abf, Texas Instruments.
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| Model based on original model for DDR_SEIOPB_V
|   Sub model SR001_DRV40_1P2
[model]   SR001_DRV40_1P2_M#51
|[Description]  [1.2V-I/O-X-X]
|   , ,
|[Input Load]
|[Output Drive]
|Voltage   1.2V
|Mode   I/O
Model_type   I/O
Polarity   Non-Inverting
Enable   Active-Low
Vinl =  0.47
Vinh =  0.73
Cref =  15.0000pF
Rref =  100.0000M
Vref =  0V
Vmeas =  0.6
C_comp   2p   2p   2p
[Model Spec]
Vinl   0.47   0.41   0.50
Vinh   0.73   0.67   0.76
[Receiver Thresholds]
Tslew_ac = 5n
Vth = 0.6
Vth_max = 0.63
Vth_min = 0.54
Vinh_ac = 0.22
Vinh_dc = 0.13
Vinl_ac = -0.22
Vinl_dc = -0.13
[Temperature Range]   25   125   -40
[Voltage Range]   1.2   1.08   1.26
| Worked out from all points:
|   slope of the pulldown table from 0 to 0.18 V, typ, clamps not added: 39.6 ohm
|   slope of the pullup table from 0 to 0.18 V, typ, clamps not added: 39.1 ohm
|   GND clamp passes 1 mA (typ) near -0.48 V on its own axis
|   POWER clamp passes 1 mA (typ) near -0.76 V on its own axis
|   rising waveform, R_fixture 50, V_fixture 1.2: 20-80 % time 93.9ps typ, 218ps min, 54ps max; typ from 0.531 V to 1.2 V
|   rising waveform, R_fixture 50, V_fixture 0: 20-80 % time 93.3ps typ, 213ps min, 53.9ps max; typ from 0 V to 0.672 V
|   falling waveform, R_fixture 50, V_fixture 1.2: 20-80 % time 93.3ps typ, 206ps min, 55.7ps max; typ from 1.2 V to 0.531 V
|   falling waveform, R_fixture 50, V_fixture 0: 20-80 % time 93.5ps typ, 209ps min, 55.3ps max; typ from 0.672 V to 0 V
[POWER_clamp]
-1.2V     148.6mA    109.7mA    235.9mA
-1.115V   108mA      79.97mA    170.5mA
-1.055V   80.16mA    59.93mA    125.3mA
-1.006V   59.04mA    45.03mA    90.73mA
-957.6mV  39.59mA    31.69mA    58.49mA
-921.2mV  26.75mA    23.11mA    36.96mA
-897mV    19.41mA    18.26mA    24.7mA
-860.6mV  10.74mA    12.35mA    10.83mA
-836.4mV  6.696mA    9.316mA    5.268mA
-787.9mV  2.052mA    4.939mA    818.3uA
-666.7mV  49.08uA    692.2uA    5.202uA
0V        48.89nA    205.6nA    269.9nA
[Pulldown]
-1.2V     -14.8mA    -14.74mA   -14.71mA
-690.9mV  -13.39mA   -13.26mA   -13.4mA
-509.1mV  -11.88mA   -11.54mA   -12.04mA
-400mV    -9.96mA    -9.599mA   -10.33mA
1.018V    25.39mA    24.35mA    26.45mA
1.527V    37.74mA    35.87mA    39.28mA
1.745V    42.94mA    40.13mA    44.66mA
1.855V    45.5mA     41.09mA    47.32mA
1.964V    47.72mA    41.01mA    49.95mA
2.073V    48.25mA    40.41mA    51.99mA
2.218V    47.89mA    39.59mA    50.92mA
2.4V      47.6mA     38.35mA    50.84mA
[Pullup]
-1.2V     21.34mA    18.16mA    23.12mA
-836.4mV  20.22mA    17.83mA    21.7mA
-763.6mV  19.2mA     17.3mA     20.39mA
-654.5mV  16.69mA    15.75mA    17.55mA
836.4mV   -21.16mA   -19.98mA   -22.26mA
1.273V    -31.93mA   -29.49mA   -33.59mA
1.527V    -38.06mA   -34.03mA   -40.07mA
1.6V      -39.68mA   -34.68mA   -41.87mA
1.709V    -41.42mA   -34.9mA    -44.05mA
1.855V    -42.44mA   -34.22mA   -45.47mA
2.036V    -42.8mA    -32.31mA   -46.22mA
2.4V      -41.95mA   -26.76mA   -45.45mA
[GND_clamp]
-1.2V     -68.74mA   -49.24mA   -125.5mA
-1.127V   -53.92mA   -35.5mA    -100.1mA
-1.055V   -39.92mA   -23.99mA   -75.5mA
-981.8mV  -27.37mA   -15.83mA   -52.4mA
-909.1mV  -17.63mA   -11.09mA   -32.41mA
-860.6mV  -13.38mA   -9.079mA   -22.59mA
-836.4mV  -11.86mA   -8.241mA   -19.18mA
-787.9mV  -9.515mA   -6.746mA   -14.76mA
-739.4mV  -7.652mA   -5.419mA   -11.95mA
-521.2mV  -1.657mA   -1.168mA   -3.09mA
-375.8mV  -108.2uA   -128.9uA   -198.1uA
1.2V      48.89nA    308.5nA    224.4nA
[Ramp]
dV/dt_f 0.40201391/93.467234p 0.35699904/0.20678552n 0.42965064/55.693017p
dV/dt_r 0.40636247/93.992414p 0.35916044/0.21589564n 0.43591744/54.232306p
R_load = 50
[Rising Waveform]
R_fixture = 50
V_fixture = 1.2
V_fixture_min = 1.08
V_fixture_max = 1.26
0s        531.3mV    487.5mV    545.8mV
40.2ps    530.7mV    487.5mV    568.2mV
110.8ps   530.2mV    487.4mV    1.109V
131.1ps   528.6mV    487.4mV    1.187V
160.5ps   572.5mV    487.4mV    1.232V
283.4ps   1.093V     487.3mV    1.256V
324.1ps   1.17V      486.7mV    1.257V
406.7ps   1.194V     502mV      1.258V
722.1ps   1.199V     1.039V     1.26V
872.3ps   1.2V       1.08V      1.26V
[Rising Waveform]
R_fixture = 50
V_fixture = 0
V_fixture_min = 0
V_fixture_max = 0
0s        0V         0V         0V
43.7ps    0V         0V         20.88mV
116.4ps   0V         0V         574.7mV
149.4ps   -2.872mV   0V         675.4mV
170.3ps   53.56mV    0V         698mV
291.4ps   568.6mV    0V         718.7mV
330ps     641.6mV    0V         719.4mV
414.9ps   667.3mV    0V         720.3mV
738.4ps   671.5mV    544.7mV    721.5mV
845.3ps   672.4mV    592.8mV    721.6mV
[Falling Waveform]
R_fixture = 50
V_fixture = 1.2
V_fixture_min = 1.08
V_fixture_max = 1.26
0s        1.2V       1.08V      1.26V
45.7ps    1.2V       1.08V      1.235V
118.1ps   1.2V       1.08V      696.2mV
137.6ps   1.201V     1.08V      622.4mV
167.8ps   1.183V     1.08V      575.1mV
298.2ps   640.4mV    1.08V      548.7mV
337.8ps   564.5mV    1.08V      547.8mV
447.9ps   536mV      1.069V     546.3mV
745.1ps   532.5mV    545.6mV    545mV
872.3ps   531.3mV    487.5mV    544.9mV
[Falling Waveform]
R_fixture = 50
V_fixture = 0
V_fixture_min = 0
V_fixture_max = 0
0s        672.4mV    592.8mV    721.6mV
43.2ps    672.6mV    592.8mV    693.4mV
114.9ps   672mV      592.8mV    147.9mV
134.1ps   672.5mV    592.8mV    75.75mV
164.6ps   651.1mV    592.8mV    28.72mV
288.9ps   122.2mV    592.8mV    3.931mV
330.1ps   34.79mV    592.6mV    2.722mV
433.3ps   4.993mV    579.2mV    0V
733.6ps   0V         47.78mV    0V
845.3ps   0V         0V         0V
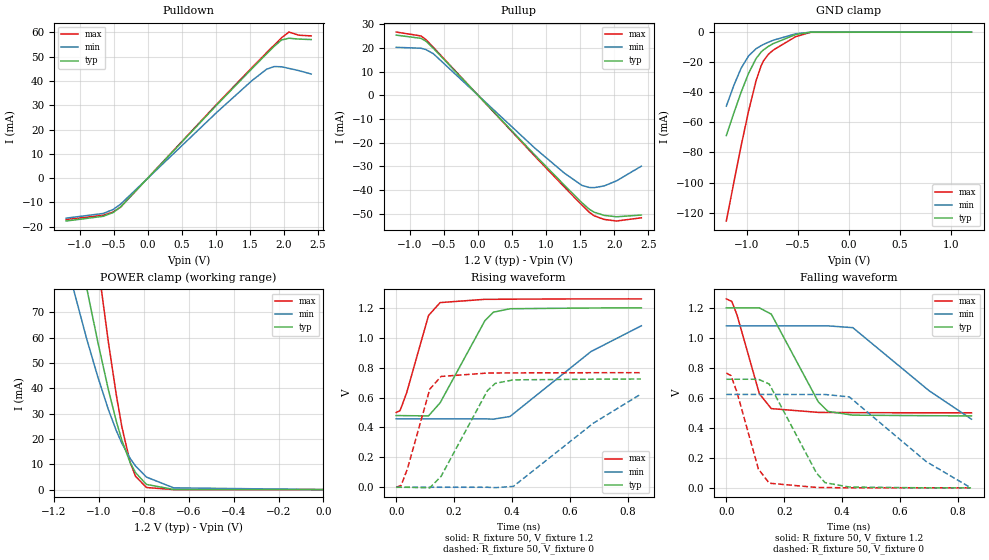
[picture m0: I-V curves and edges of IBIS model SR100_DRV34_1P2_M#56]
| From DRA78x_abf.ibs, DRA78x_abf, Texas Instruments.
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| Model based on original model for DDR_SEIOPB_V
|   Sub model SR100_DRV34_1P2
[model]   SR100_DRV34_1P2_M#56
|[Description]  [1.2V-I/O-X-X]
|   , ,
|[Input Load]
|[Output Drive]
|Voltage   1.2V
|Mode   I/O
Model_type   I/O
Polarity   Non-Inverting
Enable   Active-Low
Vinl =  0.47
Vinh =  0.73
Cref =  15.0000pF
Rref =  100.0000M
Vref =  0V
Vmeas =  0.6
C_comp   2p   2p   2p
[Model Spec]
Vinl   0.47   0.41   0.50
Vinh   0.73   0.67   0.76
[Receiver Thresholds]
Tslew_ac = 5n
Vth = 0.6
Vth_max = 0.63
Vth_min = 0.54
Vinh_ac = 0.22
Vinh_dc = 0.13
Vinl_ac = -0.22
Vinl_dc = -0.13
[Temperature Range]   25   125   -40
[Voltage Range]   1.2   1.08   1.26
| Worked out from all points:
|   slope of the pulldown table from 0 to 0.18 V, typ, clamps not added: 33.3 ohm
|   slope of the pullup table from 0 to 0.18 V, typ, clamps not added: 32.8 ohm
|   GND clamp passes 1 mA (typ) near -0.48 V on its own axis
|   POWER clamp passes 1 mA (typ) near -0.76 V on its own axis
|   rising waveform, R_fixture 50, V_fixture 1.2: 20-80 % time 120ps typ, 271ps min, 65ps max; typ from 0.48 V to 1.2 V
|   rising waveform, R_fixture 50, V_fixture 0: 20-80 % time 118ps typ, 263ps min, 64.8ps max; typ from 0 V to 0.724 V
|   falling waveform, R_fixture 50, V_fixture 1.2: 20-80 % time 117ps typ, 256ps min, 65.6ps max; typ from 1.2 V to 0.48 V
|   falling waveform, R_fixture 50, V_fixture 0: 20-80 % time 119ps typ, 260ps min, 65.4ps max; typ from 0.724 V to 0 V
[POWER_clamp]
-1.2V     148.6mA    109.7mA    235.9mA
-1.115V   108mA      79.97mA    170.5mA
-1.055V   80.16mA    59.93mA    125.3mA
-1.006V   59.04mA    45.03mA    90.73mA
-957.6mV  39.59mA    31.69mA    58.49mA
-921.2mV  26.75mA    23.11mA    36.96mA
-897mV    19.41mA    18.26mA    24.7mA
-860.6mV  10.74mA    12.35mA    10.83mA
-836.4mV  6.696mA    9.316mA    5.268mA
-787.9mV  2.052mA    4.939mA    818.3uA
-666.7mV  49.08uA    692.2uA    5.202uA
0V        48.89nA    205.6nA    269.9nA
[Pulldown]
-1.2V     -17.65mA   -16.47mA   -17.02mA
-654.5mV  -15.71mA   -14.54mA   -15.27mA
-509.1mV  -14.16mA   -12.9mA    -13.93mA
-400mV    -11.87mA   -10.73mA   -11.95mA
1.018V    30.26mA    27.21mA    30.6mA
1.527V    44.99mA    40.08mA    45.43mA
1.745V    51.18mA    44.84mA    51.66mA
1.855V    54.23mA    45.93mA    54.73mA
1.964V    56.89mA    45.84mA    57.78mA
2.073V    57.58mA    45.17mA    60.14mA
2.218V    57.24mA    44.26mA    58.83mA
2.4V      57.04mA    42.86mA    58.55mA
[Pullup]
-1.2V     25.45mA    20.3mA     26.76mA
-836.4mV  24.1mA     19.92mA    25.1mA
-763.6mV  22.89mA    19.34mA    23.58mA
-654.5mV  19.9mA     17.6mA     20.29mA
836.4mV   -25.22mA   -22.32mA   -25.74mA
1.273V    -38.05mA   -32.95mA   -38.85mA
1.527V    -45.36mA   -38.03mA   -46.35mA
1.636V    -48.14mA   -38.94mA   -49.4mA
1.709V    -49.41mA   -39mA      -50.93mA
1.855V    -50.73mA   -38.25mA   -52.44mA
2.036V    -51.3mA    -36.12mA   -53.1mA
2.4V      -50.58mA   -29.91mA   -51.74mA
[GND_clamp]
-1.2V     -68.74mA   -49.24mA   -125.5mA
-1.127V   -53.92mA   -35.5mA    -100.1mA
-1.055V   -39.92mA   -23.99mA   -75.5mA
-981.8mV  -27.37mA   -15.83mA   -52.4mA
-909.1mV  -17.63mA   -11.09mA   -32.41mA
-860.6mV  -13.38mA   -9.079mA   -22.59mA
-836.4mV  -11.86mA   -8.241mA   -19.18mA
-787.9mV  -9.515mA   -6.746mA   -14.76mA
-739.4mV  -7.652mA   -5.419mA   -11.95mA
-521.2mV  -1.657mA   -1.168mA   -3.09mA
-375.8mV  -108.2uA   -128.9uA   -198.1uA
1.2V      48.89nA    308.5nA    224.4nA
[Ramp]
dV/dt_f 0.43304814/0.11738358n 0.37482828/0.25778419n 0.45651341/65.71318p
dV/dt_r 0.43716864/0.11878008n 0.37701905/0.26708987n 0.46232241/65.235665p
R_load = 50
[Rising Waveform]
R_fixture = 50
V_fixture = 1.2
V_fixture_min = 1.08
V_fixture_max = 1.26
0s        479.6mV    457.8mV    500.4mV
13.3ps    479.5mV    457.7mV    512.6mV
35.7ps    478.8mV    457.7mV    629.2mV
111.7ps   477.3mV    457.7mV    1.149V
151.9ps   565.1mV    457.7mV    1.235V
306.6ps   1.114V     457.5mV    1.257V
336ps     1.171V     455.7mV    1.257V
393.3ps   1.194V     473.3mV    1.258V
673ps     1.199V     907.4mV    1.26V
847.4ps   1.2V       1.08V      1.26V
[Rising Waveform]
R_fixture = 50
V_fixture = 0
V_fixture_min = 0
V_fixture_max = 0
0s        0V         0V         0V
17ps      0V         0V         13.04mV
38.4ps    0V         0V         120.4mV
116.1ps   -3.861mV   0V         656.1mV
155ps     72.91mV    0V         741.1mV
315ps     645mV      0V         764mV
342.4ps   694.8mV    -2.675mV   764.3mV
405.1ps   718.4mV    6.153mV    765mV
681.3ps   722.8mV    428.4mV    766.1mV
845.3ps   724mV      622.6mV    766.3mV
[Falling Waveform]
R_fixture = 50
V_fixture = 1.2
V_fixture_min = 1.08
V_fixture_max = 1.26
0s        1.2V       1.08V      1.26V
18.7ps    1.2V       1.08V      1.243V
36.6ps    1.2V       1.08V      1.155V
114.3ps   1.2V       1.08V      626.7mV
155.5ps   1.158V     1.08V      528.3mV
317.6ps   574.1mV    1.08V      503.1mV
351.3ps   509.4mV    1.08V      502.5mV
437.3ps   484.7mV    1.068V     501.4mV
700.6ps   481mV      647.9mV    500.3mV
847.4ps   479.6mV    457.8mV    500mV
[Falling Waveform]
R_fixture = 50
V_fixture = 0
V_fixture_min = 0
V_fixture_max = 0
0s        724mV      622.6mV    765.4mV
16.2ps    724mV      622.7mV    748.2mV
36.6ps    724.1mV    622.7mV    639mV
110.6ps   724mV      622.7mV    126.7mV
148.2ps   692.5mV    622.7mV    31.06mV
311.4ps   99.49mV    622.4mV    2.702mV
341.2ps   34.53mV    622.5mV    2.087mV
425.1ps   5.378mV    606.5mV    0V
691.2ps   0V         174.8mV    0V
845.3ps   0V         0V         0V
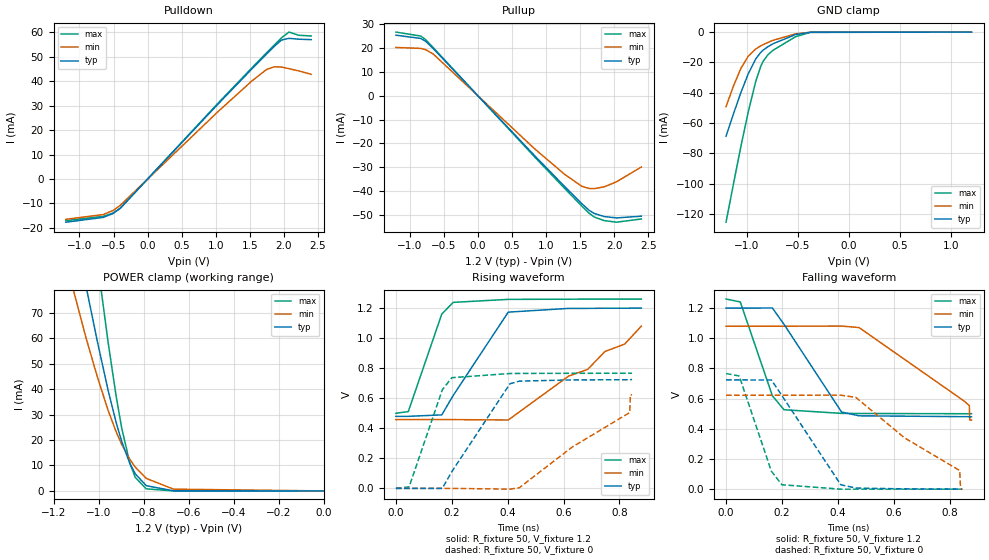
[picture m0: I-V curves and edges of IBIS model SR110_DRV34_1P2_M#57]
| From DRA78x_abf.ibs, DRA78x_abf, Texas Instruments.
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| Model based on original model for DDR_SEIOPB_V
|   Sub model SR110_DRV34_1P2
[model]   SR110_DRV34_1P2_M#57
|[Description]  [1.2V-I/O-X-X]
|   , ,
|[Input Load]
|[Output Drive]
|Voltage   1.2V
|Mode   I/O
Model_type   I/O
Polarity   Non-Inverting
Enable   Active-Low
Vinl =  0.47
Vinh =  0.73
Cref =  15.0000pF
Rref =  100.0000M
Vref =  0V
Vmeas =  0.6
C_comp   2p   2p   2p
[Model Spec]
Vinl   0.47   0.41   0.50
Vinh   0.73   0.67   0.76
[Receiver Thresholds]
Tslew_ac = 5n
Vth = 0.6
Vth_max = 0.63
Vth_min = 0.54
Vinh_ac = 0.22
Vinh_dc = 0.13
Vinl_ac = -0.22
Vinl_dc = -0.13
[Temperature Range]   25   125   -40
[Voltage Range]   1.2   1.08   1.26
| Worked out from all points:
|   slope of the pulldown table from 0 to 0.18 V, typ, clamps not added: 33.3 ohm
|   slope of the pullup table from 0 to 0.18 V, typ, clamps not added: 32.8 ohm
|   GND clamp passes 1 mA (typ) near -0.48 V on its own axis
|   POWER clamp passes 1 mA (typ) near -0.76 V on its own axis
|   rising waveform, R_fixture 50, V_fixture 1.2: 20-80 % time 149ps typ, 322ps min, 79.7ps max; typ from 0.48 V to 1.2 V
|   rising waveform, R_fixture 50, V_fixture 0: 20-80 % time 145ps typ, 313ps min, 79.1ps max; typ from 0 V to 0.724 V
|   falling waveform, R_fixture 50, V_fixture 1.2: 20-80 % time 144ps typ, 307ps min, 79.8ps max; typ from 1.2 V to 0.48 V
|   falling waveform, R_fixture 50, V_fixture 0: 20-80 % time 147ps typ, 310ps min, 80ps max; typ from 0.724 V to 0 V
[POWER_clamp]
-1.2V     148.6mA    109.7mA    235.9mA
-1.115V   108mA      79.97mA    170.5mA
-1.055V   80.16mA    59.93mA    125.3mA
-1.006V   59.04mA    45.03mA    90.73mA
-957.6mV  39.59mA    31.69mA    58.49mA
-921.2mV  26.75mA    23.11mA    36.96mA
-897mV    19.41mA    18.26mA    24.7mA
-860.6mV  10.74mA    12.35mA    10.83mA
-836.4mV  6.696mA    9.316mA    5.268mA
-787.9mV  2.052mA    4.939mA    818.3uA
-666.7mV  49.08uA    692.2uA    5.202uA
0V        48.89nA    205.6nA    269.9nA
[Pulldown]
-1.2V     -17.65mA   -16.47mA   -17.02mA
-654.5mV  -15.71mA   -14.54mA   -15.27mA
-509.1mV  -14.16mA   -12.9mA    -13.93mA
-400mV    -11.87mA   -10.73mA   -11.95mA
1.018V    30.26mA    27.21mA    30.6mA
1.527V    44.99mA    40.08mA    45.43mA
1.745V    51.18mA    44.84mA    51.66mA
1.855V    54.23mA    45.93mA    54.73mA
1.964V    56.89mA    45.84mA    57.78mA
2.073V    57.58mA    45.17mA    60.14mA
2.218V    57.24mA    44.26mA    58.83mA
2.4V      57.04mA    42.86mA    58.55mA
[Pullup]
-1.2V     25.45mA    20.3mA     26.76mA
-836.4mV  24.1mA     19.92mA    25.1mA
-763.6mV  22.89mA    19.34mA    23.58mA
-654.5mV  19.9mA     17.6mA     20.29mA
836.4mV   -25.22mA   -22.32mA   -25.74mA
1.273V    -38.05mA   -32.95mA   -38.85mA
1.527V    -45.36mA   -38.03mA   -46.35mA
1.636V    -48.14mA   -38.94mA   -49.4mA
1.709V    -49.41mA   -39mA      -50.93mA
1.855V    -50.73mA   -38.25mA   -52.44mA
2.036V    -51.3mA    -36.12mA   -53.1mA
2.4V      -50.58mA   -29.91mA   -51.74mA
[GND_clamp]
-1.2V     -68.74mA   -49.24mA   -125.5mA
-1.127V   -53.92mA   -35.5mA    -100.1mA
-1.055V   -39.92mA   -23.99mA   -75.5mA
-981.8mV  -27.37mA   -15.83mA   -52.4mA
-909.1mV  -17.63mA   -11.09mA   -32.41mA
-860.6mV  -13.38mA   -9.079mA   -22.59mA
-836.4mV  -11.86mA   -8.241mA   -19.18mA
-787.9mV  -9.515mA   -6.746mA   -14.76mA
-739.4mV  -7.652mA   -5.419mA   -11.95mA
-521.2mV  -1.657mA   -1.168mA   -3.09mA
-375.8mV  -108.2uA   -128.9uA   -198.1uA
1.2V      48.89nA    308.5nA    224.4nA
[Ramp]
dV/dt_f  0.4331416/0.14409313n 0.37502779/0.30878793n 0.45659083/79.869002p
dV/dt_r 0.43706584/0.14700411n 0.37711292/0.31809179n 0.46239868/79.648516p
R_load = 50
[Rising Waveform]
R_fixture = 50
V_fixture = 1.2
V_fixture_min = 1.08
V_fixture_max = 1.26
0s        479.6mV    457.8mV    499.9mV
44.2ps    479.6mV    457.7mV    511.1mV
164.1ps   489.1mV    457.7mV    1.16V
204.9ps   618.3mV    457.8mV    1.238V
402ps     1.173V     455.2mV    1.258V
618.5ps   1.198V     747.9mV    1.259V
686ps     1.198V     791.5mV    1.26V
748.5ps   1.199V     911.3mV    1.26V
818.8ps   1.199V     960.3mV    1.26V
878.5ps   1.2V       1.08V      1.26V
[Rising Waveform]
R_fixture = 50
V_fixture = 0
V_fixture_min = 0
V_fixture_max = 0
0s        0V         0V         0V
47.2ps    0V         0V         10mV
166ps     0V         0V         656.2mV
200.3ps   112.2mV    0V         736.8mV
408.2ps   696.3mV    -5.148mV   764.6mV
441.8ps   713.9mV    4.322mV    765mV
631.6ps   722.1mV    275.9mV    765.9mV
836.9ps   723.2mV    504.8mV    766.2mV
839.3ps   724mV      622.6mV    766.3mV
845.3ps   724mV      622.6mV    766.3mV
[Falling Waveform]
R_fixture = 50
V_fixture = 1.2
V_fixture_min = 1.08
V_fixture_max = 1.26
0s        1.2V       1.08V      1.26V
51ps      1.2V       1.08V      1.241V
165.8ps   1.201V     1.08V      619.1mV
207.3ps   1.093V     1.08V      526.5mV
413.5ps   511.2mV    1.081V     502.2mV
476.3ps   486.2mV    1.071V     501.5mV
853ps     480.5mV    583mV      500.1mV
870.7ps   480.4mV    553.8mV    500.1mV
872.5ps   479.6mV    457.8mV    500mV
878.5ps   479.6mV    457.8mV    500mV
[Falling Waveform]
R_fixture = 50
V_fixture = 0
V_fixture_min = 0
V_fixture_max = 0
0s        724mV      622.6mV    766.3mV
47.1ps    724mV      622.7mV    750.3mV
162.4ps   723.7mV    622.7mV    118.6mV
199.9ps   620.5mV    622.7mV    29.19mV
410.9ps   28.86mV    623mV      0V
464.8ps   7.402mV    608mV      0V
638.4ps   2.003mV    340.7mV    0V
836.5ps   0V         123.3mV    0V
839.3ps   0V         0V         0V
845.3ps   0V         0V         0V
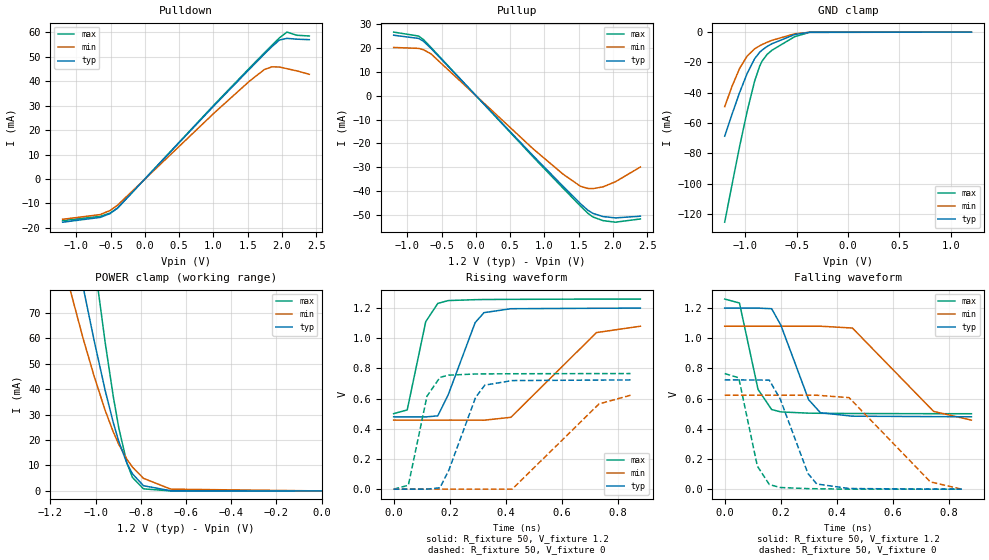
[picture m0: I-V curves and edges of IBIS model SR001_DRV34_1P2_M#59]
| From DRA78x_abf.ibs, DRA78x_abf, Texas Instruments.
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| Model based on original model for DDR_SEIOPB_V
|   Sub model SR001_DRV34_1P2
[model]   SR001_DRV34_1P2_M#59
|[Description]  [1.2V-I/O-X-X]
|   , ,
|[Input Load]
|[Output Drive]
|Voltage   1.2V
|Mode   I/O
Model_type   I/O
Polarity   Non-Inverting
Enable   Active-Low
Vinl =  0.47
Vinh =  0.73
Cref =  15.0000pF
Rref =  100.0000M
Vref =  0V
Vmeas =  0.6
C_comp   2p   2p   2p
[Model Spec]
Vinl   0.47   0.41   0.50
Vinh   0.73   0.67   0.76
[Receiver Thresholds]
Tslew_ac = 5n
Vth = 0.6
Vth_max = 0.63
Vth_min = 0.54
Vinh_ac = 0.22
Vinh_dc = 0.13
Vinl_ac = -0.22
Vinl_dc = -0.13
[Temperature Range]   25   125   -40
[Voltage Range]   1.2   1.08   1.26
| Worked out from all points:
|   slope of the pulldown table from 0 to 0.18 V, typ, clamps not added: 33.3 ohm
|   slope of the pullup table from 0 to 0.18 V, typ, clamps not added: 32.8 ohm
|   GND clamp passes 1 mA (typ) near -0.48 V on its own axis
|   POWER clamp passes 1 mA (typ) near -0.76 V on its own axis
|   rising waveform, R_fixture 50, V_fixture 1.2: 20-80 % time 86.2ps typ, 203ps min, 48.2ps max; typ from 0.48 V to 1.2 V
|   rising waveform, R_fixture 50, V_fixture 0: 20-80 % time 85.6ps typ, 197ps min, 48.3ps max; typ from 0 V to 0.724 V
|   falling waveform, R_fixture 50, V_fixture 1.2: 20-80 % time 85.7ps typ, 191ps min, 50.2ps max; typ from 1.2 V to 0.48 V
|   falling waveform, R_fixture 50, V_fixture 0: 20-80 % time 86.1ps typ, 194ps min, 49.6ps max; typ from 0.724 V to 0 V
[POWER_clamp]
-1.2V     148.6mA    109.7mA    235.9mA
-1.115V   108mA      79.97mA    170.5mA
-1.055V   80.16mA    59.93mA    125.3mA
-1.006V   59.04mA    45.03mA    90.73mA
-957.6mV  39.59mA    31.69mA    58.49mA
-921.2mV  26.75mA    23.11mA    36.96mA
-897mV    19.41mA    18.26mA    24.7mA
-860.6mV  10.74mA    12.35mA    10.83mA
-836.4mV  6.696mA    9.316mA    5.268mA
-787.9mV  2.052mA    4.939mA    818.3uA
-666.7mV  49.08uA    692.2uA    5.202uA
0V        48.89nA    205.6nA    269.9nA
[Pulldown]
-1.2V     -17.65mA   -16.47mA   -17.02mA
-654.5mV  -15.71mA   -14.54mA   -15.27mA
-509.1mV  -14.16mA   -12.9mA    -13.93mA
-400mV    -11.87mA   -10.73mA   -11.95mA
1.018V    30.26mA    27.21mA    30.6mA
1.527V    44.99mA    40.08mA    45.43mA
1.745V    51.18mA    44.84mA    51.66mA
1.855V    54.23mA    45.93mA    54.73mA
1.964V    56.89mA    45.84mA    57.78mA
2.073V    57.58mA    45.17mA    60.14mA
2.218V    57.24mA    44.26mA    58.83mA
2.4V      57.04mA    42.86mA    58.55mA
[Pullup]
-1.2V     25.45mA    20.3mA     26.76mA
-836.4mV  24.1mA     19.92mA    25.1mA
-763.6mV  22.89mA    19.34mA    23.58mA
-654.5mV  19.9mA     17.6mA     20.29mA
836.4mV   -25.22mA   -22.32mA   -25.74mA
1.273V    -38.05mA   -32.95mA   -38.85mA
1.527V    -45.36mA   -38.03mA   -46.35mA
1.636V    -48.14mA   -38.94mA   -49.4mA
1.709V    -49.41mA   -39mA      -50.93mA
1.855V    -50.73mA   -38.25mA   -52.44mA
2.036V    -51.3mA    -36.12mA   -53.1mA
2.4V      -50.58mA   -29.91mA   -51.74mA
[GND_clamp]
-1.2V     -68.74mA   -49.24mA   -125.5mA
-1.127V   -53.92mA   -35.5mA    -100.1mA
-1.055V   -39.92mA   -23.99mA   -75.5mA
-981.8mV  -27.37mA   -15.83mA   -52.4mA
-909.1mV  -17.63mA   -11.09mA   -32.41mA
-860.6mV  -13.38mA   -9.079mA   -22.59mA
-836.4mV  -11.86mA   -8.241mA   -19.18mA
-787.9mV  -9.515mA   -6.746mA   -14.76mA
-739.4mV  -7.652mA   -5.419mA   -11.95mA
-521.2mV  -1.657mA   -1.168mA   -3.09mA
-375.8mV  -108.2uA   -128.9uA   -198.1uA
1.2V      48.89nA    308.5nA    224.4nA
[Ramp]
dV/dt_f  0.4329815/85.856618p 0.37478342/0.19212973n 0.45645502/50.234274p
dV/dt_r 0.43728694/86.147927p 0.37699184/0.19959657n 0.46284696/48.587168p
R_load = 50
[Rising Waveform]
R_fixture = 50
V_fixture = 1.2
V_fixture_min = 1.08
V_fixture_max = 1.26
0s        479.6mV    457.8mV    500.7mV
48.4ps    479mV      457.7mV    525.1mV
114.4ps   478.8mV    457.7mV    1.11V
157.4ps   485.9mV    457.7mV    1.231V
194.4ps   624.8mV    457.8mV    1.25V
290.8ps   1.104V     457.6mV    1.256V
322.2ps   1.17V      457.1mV    1.257V
418.2ps   1.196V     476.2mV    1.258V
723.6ps   1.199V     1.038V     1.26V
880.1ps   1.2V       1.08V      1.26V
[Rising Waveform]
R_fixture = 50
V_fixture = 0
V_fixture_min = 0
V_fixture_max = 0
0s        0V         0V         0V
52.5ps    0V         0V         25.96mV
118.8ps   0V         0V         615.8mV
165.2ps   9.364mV    0V         741mV
196.8ps   125.7mV    0V         756mV
292.2ps   607.6mV    0V         763.3mV
325.1ps   689.5mV    0V         763.9mV
422.8ps   719.8mV    0V         765mV
732.7ps   723mV      565.3mV    766.1mV
845.3ps   724mV      622.6mV    766.3mV
[Falling Waveform]
R_fixture = 50
V_fixture = 1.2
V_fixture_min = 1.08
V_fixture_max = 1.26
0s        1.2V       1.08V      1.26V
52.6ps    1.2V       1.08V      1.234V
119ps     1.2V       1.08V      660.8mV
167.4ps   1.196V     1.08V      527.9mV
200.4ps   1.087V     1.08V      511.9mV
299.4ps   592.8mV    1.08V      503.8mV
341.8ps   506.2mV    1.08V      502.9mV
455.6ps   483.8mV    1.068V     501.4mV
745.4ps   480.8mV    515.2mV    500.2mV
880.1ps   479.6mV    457.8mV    500mV
[Falling Waveform]
R_fixture = 50
V_fixture = 0
V_fixture_min = 0
V_fixture_max = 0
0s        724mV      622.6mV    766.3mV
50ps      724.1mV    622.7mV    738.3mV
116.4ps   723.6mV    622.7mV    153.3mV
159.2ps   722.5mV    622.7mV    30.75mV
198.1ps   597.4mV    622.7mV    10.93mV
296.8ps   104.4mV    622.7mV    3.545mV
328.5ps   34.19mV    622.5mV    2.712mV
443.7ps   4.333mV    606.5mV    0V
733.7ps   0V         48.22mV    0V
845.3ps   0V         0V         0V
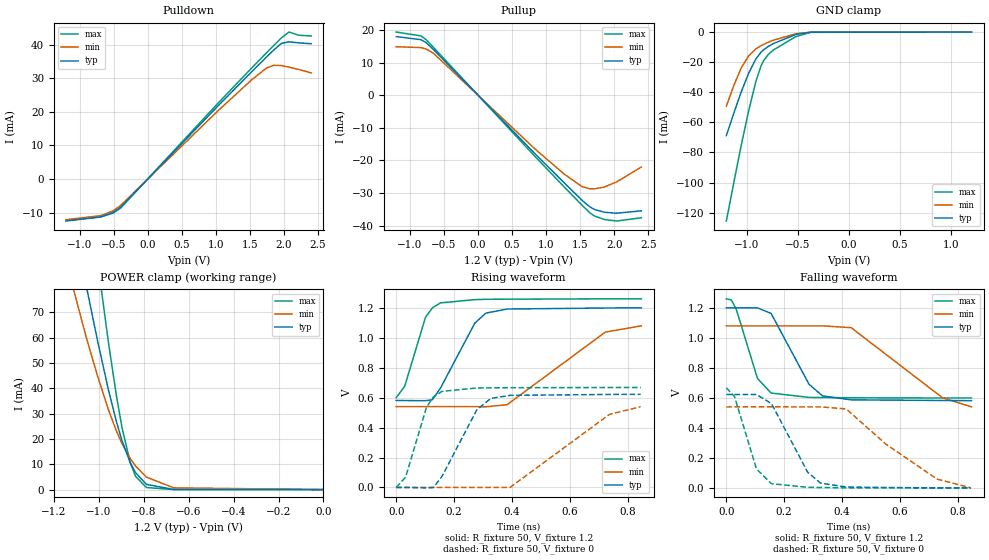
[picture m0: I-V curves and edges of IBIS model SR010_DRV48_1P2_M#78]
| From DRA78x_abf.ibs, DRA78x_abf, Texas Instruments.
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| Model based on original model for DDR_SEIOPB_V
|   Sub model SR010_DRV48_1P2
[model]   SR010_DRV48_1P2_M#78
|[Description]  [1.2V-I/O-X-X]
|   , ,
|[Input Load]
|[Output Drive]
|Voltage   1.2V
|Mode   I/O
Model_type   I/O
Polarity   Non-Inverting
Enable   Active-Low
Vinl =  0.47
Vinh =  0.73
Cref =  15.0000pF
Rref =  100.0000M
Vref =  0V
Vmeas =  0.6
C_comp   2p   2p   2p
[Model Spec]
Vinl   0.47   0.41   0.50
Vinh   0.73   0.67   0.76
[Receiver Thresholds]
Tslew_ac = 5n
Vth = 0.6
Vth_max = 0.63
Vth_min = 0.54
Vinh_ac = 0.22
Vinh_dc = 0.13
Vinl_ac = -0.22
Vinl_dc = -0.13
[Temperature Range]   25   125   -40
[Voltage Range]   1.2   1.08   1.26
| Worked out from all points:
|   slope of the pulldown table from 0 to 0.18 V, typ, clamps not added: 46.8 ohm
|   slope of the pullup table from 0 to 0.18 V, typ, clamps not added: 46.2 ohm
|   GND clamp passes 1 mA (typ) near -0.48 V on its own axis
|   POWER clamp passes 1 mA (typ) near -0.76 V on its own axis
|   rising waveform, R_fixture 50, V_fixture 1.2: 20-80 % time 98.5ps typ, 233ps min, 60.6ps max; typ from 0.581 V to 1.2 V
|   rising waveform, R_fixture 50, V_fixture 0: 20-80 % time 98ps typ, 226ps min, 60.6ps max; typ from 0 V to 0.622 V
|   falling waveform, R_fixture 50, V_fixture 1.2: 20-80 % time 98.5ps typ, 219ps min, 61.9ps max; typ from 1.2 V to 0.581 V
|   falling waveform, R_fixture 50, V_fixture 0: 20-80 % time 98.5ps typ, 224ps min, 61.2ps max; typ from 0.622 V to 0 V
[POWER_clamp]
-1.2V     148.6mA    109.7mA    235.9mA
-1.115V   108mA      79.97mA    170.5mA
-1.055V   80.16mA    59.93mA    125.3mA
-1.006V   59.04mA    45.03mA    90.73mA
-957.6mV  39.59mA    31.69mA    58.49mA
-921.2mV  26.75mA    23.11mA    36.96mA
-897mV    19.41mA    18.26mA    24.7mA
-860.6mV  10.74mA    12.35mA    10.83mA
-836.4mV  6.696mA    9.316mA    5.268mA
-787.9mV  2.052mA    4.939mA    818.3uA
-666.7mV  49.08uA    692.2uA    5.202uA
0V        48.89nA    205.6nA    269.9nA
[Pulldown]
-1.2V     -12.53mA   -12.14mA   -12.38mA
-690.9mV  -11.33mA   -10.92mA   -11.28mA
-509.1mV  -10.05mA   -9.509mA   -10.14mA
-400mV    -8.43mA    -7.908mA   -8.698mA
1.018V    21.49mA    20.06mA    22.27mA
1.527V    31.95mA    29.55mA    33.07mA
1.745V    36.35mA    33.05mA    37.6mA
1.855V    38.51mA    33.85mA    39.84mA
1.964V    40.39mA    33.77mA    42.05mA
2.073V    40.83mA    33.28mA    43.75mA
2.218V    40.52mA    32.6mA     42.79mA
2.4V      40.27mA    31.57mA    42.58mA
[Pullup]
-1.2V     18.06mA    14.95mA    19.46mA
-836.4mV  17.11mA    14.68mA    18.27mA
-763.6mV  16.25mA    14.25mA    17.17mA
-654.5mV  14.13mA    12.98mA    14.77mA
836.4mV   -17.91mA   -16.46mA   -18.74mA
1.273V    -27.02mA   -24.3mA    -28.28mA
1.527V    -32.21mA   -28.03mA   -33.73mA
1.636V    -34.17mA   -28.69mA   -35.95mA
1.709V    -35.05mA   -28.74mA   -37.06mA
1.855V    -35.92mA   -28.18mA   -38.15mA
2.036V    -36.22mA   -26.61mA   -38.62mA
2.4V      -35.49mA   -22.03mA   -37.62mA
[GND_clamp]
-1.2V     -68.74mA   -49.24mA   -125.5mA
-1.127V   -53.92mA   -35.5mA    -100.1mA
-1.055V   -39.92mA   -23.99mA   -75.5mA
-981.8mV  -27.37mA   -15.83mA   -52.4mA
-909.1mV  -17.63mA   -11.09mA   -32.41mA
-860.6mV  -13.38mA   -9.079mA   -22.59mA
-836.4mV  -11.86mA   -8.241mA   -19.18mA
-787.9mV  -9.515mA   -6.746mA   -14.76mA
-739.4mV  -7.652mA   -5.419mA   -11.95mA
-521.2mV  -1.657mA   -1.168mA   -3.09mA
-375.8mV  -108.2uA   -128.9uA   -198.1uA
1.2V      48.89nA    308.5nA    224.4nA
[Ramp]
dV/dt_f 0.37181813/98.6741p   0.32516363/0.22055408n 0.39695436/61.958525p
dV/dt_r 0.37588107/98.701771p 0.32686114/0.22879345n 0.40282078/60.992987p
R_load = 50
[Rising Waveform]
R_fixture = 50
V_fixture = 1.2
V_fixture_min = 1.08
V_fixture_max = 1.26
0s        581.3mV    540.1mV    599.8mV
29.4ps    580.6mV    540mV      676.3mV
101.1ps   579.5mV    540mV      1.136V
125ps     586.3mV    540mV      1.2V
153.1ps   664.2mV    540mV      1.233V
271.7ps   1.098V     539.9mV    1.255V
310.1ps   1.165V     539.1mV    1.257V
383.4ps   1.192V     553mV      1.258V
722.9ps   1.199V     1.038V     1.26V
847.5ps   1.2V       1.08V      1.26V
[Rising Waveform]
R_fixture = 50
V_fixture = 0
V_fixture_min = 0
V_fixture_max = 0
0s        0V         0V         0V
32.6ps    0V         0V         69.56mV
104.8ps   -2.551mV   0V         536.3mV
129.1ps   0V         0V         605.9mV
158.6ps   75mV       0V         642.1mV
278.5ps   518.1mV    0V         664.8mV
327ps     594.8mV    0V         665.7mV
393.3ps   615.4mV    0V         666.4mV
737.3ps   621.5mV    488.4mV    667.6mV
845.3ps   622.4mV    539.9mV    667.6mV
[Falling Waveform]
R_fixture = 50
V_fixture = 1.2
V_fixture_min = 1.08
V_fixture_max = 1.26
0s        1.2V       1.08V      1.26V
17.1ps    1.2V       1.08V      1.253V
33.8ps    1.2V       1.08V      1.194V
107.7ps   1.2V       1.08V      729.6mV
154.7ps   1.163V     1.08V      632mV
285.8ps   690.9mV    1.08V      603mV
332.4ps   613.2mV    1.08V      601.8mV
431.4ps   586.8mV    1.068V     600.5mV
747.6ps   582.4mV    600.1mV    599.1mV
847.5ps   581.3mV    540.1mV    599mV
[Falling Waveform]
R_fixture = 50
V_fixture = 0
V_fixture_min = 0
V_fixture_max = 0
0s        622.4mV    539.9mV    666.9mV
28.3ps    622.6mV    540mV      608.3mV
104.2ps   622.3mV    540mV      126mV
155.9ps   562.3mV    540mV      27.55mV
281.4ps   103.6mV    539.9mV    3.44mV
325.8ps   31.35mV    539.8mV    2.222mV
414.5ps   6.082mV    526.3mV    0V
550.3ps   2.244mV    293.2mV    0V
728.3ps   0V         58.37mV    0V
845.3ps   0V         0V         0V
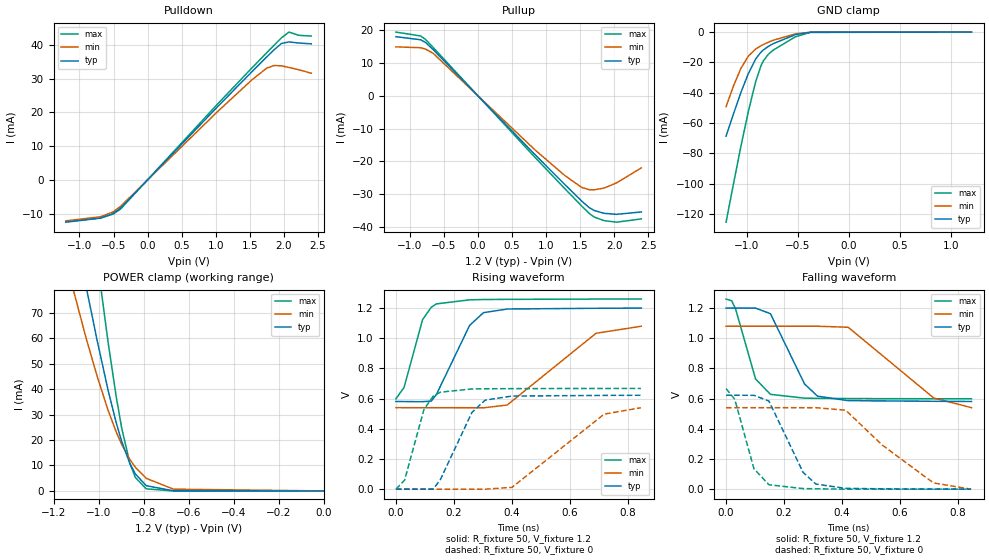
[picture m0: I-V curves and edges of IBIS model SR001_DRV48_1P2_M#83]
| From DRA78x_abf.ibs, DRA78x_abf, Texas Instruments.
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| Model based on original model for DDR_SEIOPB_V
|   Sub model SR001_DRV48_1P2
[model]   SR001_DRV48_1P2_M#83
|[Description]  [1.2V-I/O-X-X]
|   , ,
|[Input Load]
|[Output Drive]
|Voltage   1.2V
|Mode   I/O
Model_type   I/O
Polarity   Non-Inverting
Enable   Active-Low
Vinl =  0.47
Vinh =  0.73
Cref =  15.0000pF
Rref =  100.0000M
Vref =  0V
Vmeas =  0.6
C_comp   2p   2p   2p
[Model Spec]
Vinl   0.47   0.41   0.50
Vinh   0.73   0.67   0.76
[Receiver Thresholds]
Tslew_ac = 5n
Vth = 0.6
Vth_max = 0.63
Vth_min = 0.54
Vinh_ac = 0.22
Vinh_dc = 0.13
Vinl_ac = -0.22
Vinl_dc = -0.13
[Temperature Range]   25   125   -40
[Voltage Range]   1.2   1.08   1.26
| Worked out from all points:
|   slope of the pulldown table from 0 to 0.18 V, typ, clamps not added: 46.8 ohm
|   slope of the pullup table from 0 to 0.18 V, typ, clamps not added: 46.2 ohm
|   GND clamp passes 1 mA (typ) near -0.48 V on its own axis
|   POWER clamp passes 1 mA (typ) near -0.76 V on its own axis
|   rising waveform, R_fixture 50, V_fixture 1.2: 20-80 % time 89.3ps typ, 210ps min, 56.1ps max; typ from 0.581 V to 1.2 V
|   rising waveform, R_fixture 50, V_fixture 0: 20-80 % time 89.1ps typ, 205ps min, 56.1ps max; typ from 0 V to 0.622 V
|   falling waveform, R_fixture 50, V_fixture 1.2: 20-80 % time 89.9ps typ, 200ps min, 57.8ps max; typ from 1.2 V to 0.581 V
|   falling waveform, R_fixture 50, V_fixture 0: 20-80 % time 89.5ps typ, 203ps min, 57ps max; typ from 0.622 V to 0 V
[POWER_clamp]
-1.2V     148.6mA    109.7mA    235.9mA
-1.115V   108mA      79.97mA    170.5mA
-1.055V   80.16mA    59.93mA    125.3mA
-1.006V   59.04mA    45.03mA    90.73mA
-957.6mV  39.59mA    31.69mA    58.49mA
-921.2mV  26.75mA    23.11mA    36.96mA
-897mV    19.41mA    18.26mA    24.7mA
-860.6mV  10.74mA    12.35mA    10.83mA
-836.4mV  6.696mA    9.316mA    5.268mA
-787.9mV  2.052mA    4.939mA    818.3uA
-666.7mV  49.08uA    692.2uA    5.202uA
0V        48.89nA    205.6nA    269.9nA
[Pulldown]
-1.2V     -12.53mA   -12.14mA   -12.38mA
-690.9mV  -11.33mA   -10.92mA   -11.28mA
-509.1mV  -10.05mA   -9.509mA   -10.14mA
-400mV    -8.43mA    -7.908mA   -8.698mA
1.018V    21.49mA    20.06mA    22.27mA
1.527V    31.95mA    29.55mA    33.07mA
1.745V    36.35mA    33.05mA    37.6mA
1.855V    38.51mA    33.85mA    39.84mA
1.964V    40.39mA    33.77mA    42.05mA
2.073V    40.83mA    33.28mA    43.75mA
2.218V    40.52mA    32.6mA     42.79mA
2.4V      40.27mA    31.57mA    42.58mA
[Pullup]
-1.2V     18.06mA    14.95mA    19.46mA
-836.4mV  17.11mA    14.68mA    18.27mA
-763.6mV  16.25mA    14.25mA    17.17mA
-654.5mV  14.13mA    12.98mA    14.77mA
836.4mV   -17.91mA   -16.46mA   -18.74mA
1.273V    -27.02mA   -24.3mA    -28.28mA
1.527V    -32.21mA   -28.03mA   -33.73mA
1.636V    -34.17mA   -28.69mA   -35.95mA
1.709V    -35.05mA   -28.74mA   -37.06mA
1.855V    -35.92mA   -28.18mA   -38.15mA
2.036V    -36.22mA   -26.61mA   -38.62mA
2.4V      -35.49mA   -22.03mA   -37.62mA
[GND_clamp]
-1.2V     -68.74mA   -49.24mA   -125.5mA
-1.127V   -53.92mA   -35.5mA    -100.1mA
-1.055V   -39.92mA   -23.99mA   -75.5mA
-981.8mV  -27.37mA   -15.83mA   -52.4mA
-909.1mV  -17.63mA   -11.09mA   -32.41mA
-860.6mV  -13.38mA   -9.079mA   -22.59mA
-836.4mV  -11.86mA   -8.241mA   -19.18mA
-787.9mV  -9.515mA   -6.746mA   -14.76mA
-739.4mV  -7.652mA   -5.419mA   -11.95mA
-521.2mV  -1.657mA   -1.168mA   -3.09mA
-375.8mV  -108.2uA   -128.9uA   -198.1uA
1.2V      48.89nA    308.5nA    224.4nA
[Ramp]
dV/dt_f 0.37178981/90.068519p 0.32513199/0.2004497n 0.39695183/57.858821p
dV/dt_r 0.37584733/89.605393p 0.32687876/0.2070619n 0.40284796/56.447625p
R_load = 50
[Rising Waveform]
R_fixture = 50
V_fixture = 1.2
V_fixture_min = 1.08
V_fixture_max = 1.26
0s        581.3mV    540.1mV    599mV
28ps      580.6mV    540mV      673.9mV
92ps      579.8mV    540mV      1.124V
122ps     584.2mV    540mV      1.206V
140ps     628.7mV    540mV      1.228V
254.4ps   1.086V     539.9mV    1.255V
302.3ps   1.17V      539.2mV    1.257V
383.8ps   1.194V     557.6mV    1.258V
690.1ps   1.199V     1.033V     1.26V
846.7ps   1.2V       1.08V      1.26V
[Rising Waveform]
R_fixture = 50
V_fixture = 0
V_fixture_min = 0
V_fixture_max = 0
0s        0V         0V         0V
30.1ps    0V         0V         60.6mV
96.6ps    0V         0V         527.7mV
128.9ps   0V         0V         617.1mV
154ps     66.41mV    0V         643.1mV
262.2ps   508.7mV    0V         664.3mV
308ps     590.4mV    0V         665.4mV
400.7ps   617.1mV    12.05mV    666.4mV
718.6ps   621.5mV    497.6mV    667.5mV
845.3ps   622.4mV    539.9mV    667.6mV
[Falling Waveform]
R_fixture = 50
V_fixture = 1.2
V_fixture_min = 1.08
V_fixture_max = 1.26
0s        1.2V       1.08V      1.26V
19.3ps    1.2V       1.08V      1.249V
32.8ps    1.2V       1.08V      1.195V
101.9ps   1.2V       1.08V      730.2mV
153.2ps   1.163V     1.08V      628.5mV
270.8ps   697.3mV    1.08V      603.2mV
315.4ps   616.6mV    1.08V      602mV
421.5ps   586.6mV    1.073V     600.5mV
716.3ps   582.5mV    604.6mV    599.2mV
846.7ps   581.3mV    540.1mV    599mV
[Falling Waveform]
R_fixture = 50
V_fixture = 0
V_fixture_min = 0
V_fixture_max = 0
0s        622.4mV    539.9mV    666.9mV
30ps      622.6mV    540mV      595.9mV
96.3ps    622.1mV    540mV      135mV
147.9ps   583.9mV    540mV      29.3mV
265.8ps   111.2mV    540mV      3.762mV
309.9ps   33.76mV    539.8mV    2.434mV
412.6ps   5.404mV    523.4mV    0V
539.1ps   2.249mV    292mV      0V
715.9ps   0V         40.95mV    0V
845.3ps   0V         0V         0V
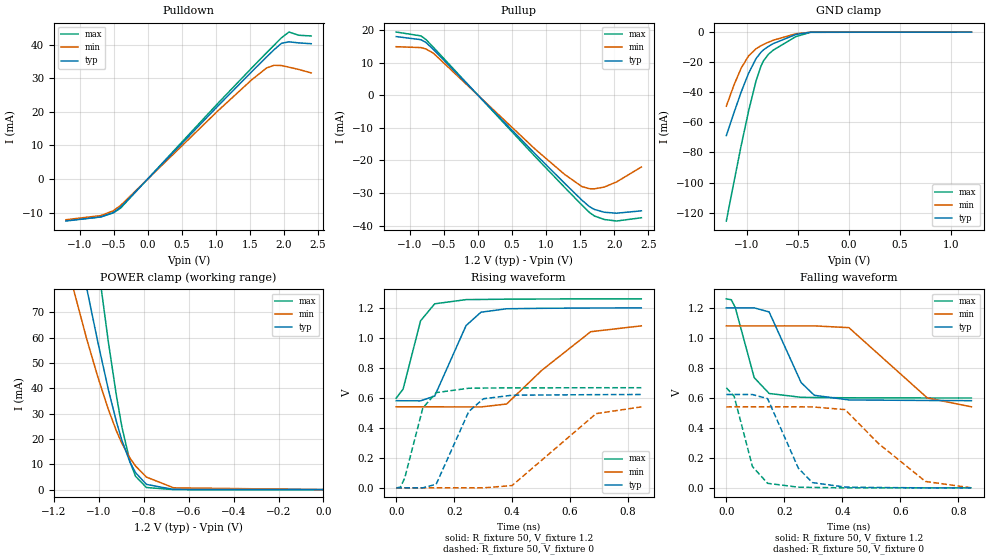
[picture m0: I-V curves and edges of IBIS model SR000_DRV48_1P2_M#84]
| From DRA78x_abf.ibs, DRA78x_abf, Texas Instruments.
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| Model based on original model for DDR_SEIOPB_V
|   Sub model SR000_DRV48_1P2
[model]   SR000_DRV48_1P2_M#84
|[Description]  [1.2V-I/O-X-X]
|   , ,
|[Input Load]
|[Output Drive]
|Voltage   1.2V
|Mode   I/O
Model_type   I/O
Polarity   Non-Inverting
Enable   Active-Low
Vinl =  0.47
Vinh =  0.73
Cref =  15.0000pF
Rref =  100.0000M
Vref =  0V
Vmeas =  0.6
C_comp   2p   2p   2p
[Model Spec]
Vinl   0.47   0.41   0.50
Vinh   0.73   0.67   0.76
[Receiver Thresholds]
Tslew_ac = 5n
Vth = 0.6
Vth_max = 0.63
Vth_min = 0.54
Vinh_ac = 0.22
Vinh_dc = 0.13
Vinl_ac = -0.22
Vinl_dc = -0.13
[Temperature Range]   25   125   -40
[Voltage Range]   1.2   1.08   1.26
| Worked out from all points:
|   slope of the pulldown table from 0 to 0.18 V, typ, clamps not added: 46.8 ohm
|   slope of the pullup table from 0 to 0.18 V, typ, clamps not added: 46.2 ohm
|   GND clamp passes 1 mA (typ) near -0.48 V on its own axis
|   POWER clamp passes 1 mA (typ) near -0.76 V on its own axis
|   rising waveform, R_fixture 50, V_fixture 1.2: 20-80 % time 81.4ps typ, 190ps min, 52.6ps max; typ from 0.581 V to 1.2 V
|   rising waveform, R_fixture 50, V_fixture 0: 20-80 % time 81.4ps typ, 187ps min, 52.5ps max; typ from 0 V to 0.622 V
|   falling waveform, R_fixture 50, V_fixture 1.2: 20-80 % time 82.8ps typ, 181ps min, 54.7ps max; typ from 1.2 V to 0.581 V
|   falling waveform, R_fixture 50, V_fixture 0: 20-80 % time 82.3ps typ, 183ps min, 53.7ps max; typ from 0.622 V to 0 V
[POWER_clamp]
-1.2V     148.6mA    109.7mA    235.9mA
-1.115V   108mA      79.97mA    170.5mA
-1.055V   80.16mA    59.93mA    125.3mA
-1.006V   59.04mA    45.03mA    90.73mA
-957.6mV  39.59mA    31.69mA    58.49mA
-921.2mV  26.75mA    23.11mA    36.96mA
-897mV    19.41mA    18.26mA    24.7mA
-860.6mV  10.74mA    12.35mA    10.83mA
-836.4mV  6.696mA    9.316mA    5.268mA
-787.9mV  2.052mA    4.939mA    818.3uA
-666.7mV  49.08uA    692.2uA    5.202uA
0V        48.89nA    205.6nA    269.9nA
[Pulldown]
-1.2V     -12.53mA   -12.14mA   -12.38mA
-690.9mV  -11.33mA   -10.92mA   -11.28mA
-509.1mV  -10.05mA   -9.509mA   -10.14mA
-400mV    -8.43mA    -7.908mA   -8.698mA
1.018V    21.49mA    20.06mA    22.27mA
1.527V    31.95mA    29.55mA    33.07mA
1.745V    36.35mA    33.05mA    37.6mA
1.855V    38.51mA    33.85mA    39.84mA
1.964V    40.39mA    33.77mA    42.05mA
2.073V    40.83mA    33.28mA    43.75mA
2.218V    40.52mA    32.6mA     42.79mA
2.4V      40.27mA    31.57mA    42.58mA
[Pullup]
-1.2V     18.06mA    14.95mA    19.46mA
-836.4mV  17.11mA    14.68mA    18.27mA
-763.6mV  16.25mA    14.25mA    17.17mA
-654.5mV  14.13mA    12.98mA    14.77mA
836.4mV   -17.91mA   -16.46mA   -18.74mA
1.273V    -27.02mA   -24.3mA    -28.28mA
1.527V    -32.21mA   -28.03mA   -33.73mA
1.636V    -34.17mA   -28.69mA   -35.95mA
1.709V    -35.05mA   -28.74mA   -37.06mA
1.855V    -35.92mA   -28.18mA   -38.15mA
2.036V    -36.22mA   -26.61mA   -38.62mA
2.4V      -35.49mA   -22.03mA   -37.62mA
[GND_clamp]
-1.2V     -68.74mA   -49.24mA   -125.5mA
-1.127V   -53.92mA   -35.5mA    -100.1mA
-1.055V   -39.92mA   -23.99mA   -75.5mA
-981.8mV  -27.37mA   -15.83mA   -52.4mA
-909.1mV  -17.63mA   -11.09mA   -32.41mA
-860.6mV  -13.38mA   -9.079mA   -22.59mA
-836.4mV  -11.86mA   -8.241mA   -19.18mA
-787.9mV  -9.515mA   -6.746mA   -14.76mA
-739.4mV  -7.652mA   -5.419mA   -11.95mA
-521.2mV  -1.657mA   -1.168mA   -3.09mA
-375.8mV  -108.2uA   -128.9uA   -198.1uA
1.2V      48.89nA    308.5nA    224.4nA
[Ramp]
dV/dt_f 0.37180129/82.946142p  0.3251012/0.18179802n 0.39696287/54.708348p
dV/dt_r 0.37608359/81.972666p 0.32700373/0.18837958n 0.40291033/52.826108p
R_load = 50
[Rising Waveform]
R_fixture = 50
V_fixture = 1.2
V_fixture_min = 1.08
V_fixture_max = 1.26
0s        581.3mV    540.1mV    598.3mV
23.7ps    580.6mV    540mV      657.9mV
84.1ps    580.1mV    540mV      1.114V
132.6ps   611.7mV    540mV      1.227V
241ps     1.082V     539.8mV    1.255V
292.2ps   1.171V     539.4mV    1.256V
380.8ps   1.194V     558.9mV    1.258V
501.9ps   1.197V     783.3mV    1.259V
670.8ps   1.199V     1.041V     1.26V
845.3ps   1.2V       1.08V      1.26V
[Rising Waveform]
R_fixture = 50
V_fixture = 0
V_fixture_min = 0
V_fixture_max = 0
0s        0V         0V         0V
14.5ps    0V         0V         4.467mV
29.4ps    0V         0V         65.43mV
91.7ps    0V         0V         531.7mV
137.9ps   24.15mV    0V         635mV
250.4ps   509.5mV    0V         664.2mV
300.7ps   594mV      0V         665.4mV
399.7ps   617.7mV    15.34mV    666.5mV
689.5ps   621.4mV    494.9mV    667.5mV
845.6ps   622.4mV    539.9mV    667.6mV
[Falling Waveform]
R_fixture = 50
V_fixture = 1.2
V_fixture_min = 1.08
V_fixture_max = 1.26
0s        1.2V       1.08V      1.26V
17.2ps    1.2V       1.08V      1.254V
30.9ps    1.2V       1.08V      1.202V
96.1ps    1.2V       1.08V      734.9mV
147.6ps   1.173V     1.08V      629.3mV
257.9ps   702mV      1.08V      603.7mV
303.6ps   617mV      1.08V      602.2mV
422.8ps   586.1mV    1.068V     600.4mV
693.2ps   582.6mV    599.5mV    599.2mV
845.3ps   581.3mV    540.1mV    599mV
[Falling Waveform]
R_fixture = 50
V_fixture = 0
V_fixture_min = 0
V_fixture_max = 0
0s        622.4mV    539.9mV    666.9mV
26.8ps    622.6mV    540mV      611.2mV
90ps      622.1mV    540mV      142.2mV
142.4ps   594.8mV    540mV      30.14mV
248.5ps   130.8mV    540mV      4.44mV
296.6ps   35.21mV    539.8mV    2.722mV
409.7ps   5.042mV    521.7mV    0V
524.5ps   2.324mV    295.9mV    0V
686.8ps   0V         42.62mV    0V
845.6ps   0V         0V         0V
